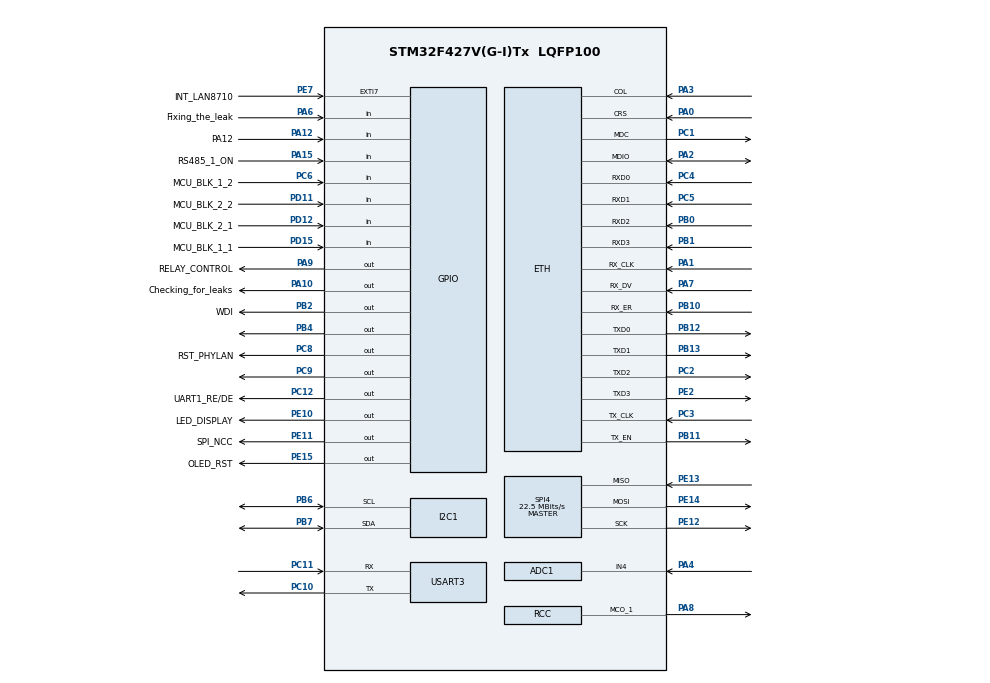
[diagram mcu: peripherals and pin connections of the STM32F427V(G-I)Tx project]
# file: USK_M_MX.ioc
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ADC1.Channel-0\#ChannelRegularConversion=ADC_CHANNEL_4
ADC1.NbrOfConversionFlag=1
ADC1.Rank-0\#ChannelRegularConversion=1
ADC1.SamplingTime-0\#ChannelRegularConversion=ADC_SAMPLETIME_3CYCLES
ADC1.master=1
Dma.Request0=SPI4_TX
Dma.Request1=USART3_RX
Dma.Request2=USART3_TX
Dma.SPI4_TX.0.Direction=DMA_MEMORY_TO_PERIPH
Dma.SPI4_TX.0.FIFOMode=DMA_FIFOMODE_DISABLE
Dma.SPI4_TX.0.Instance=DMA2_Stream1
Dma.SPI4_TX.0.MemDataAlignment=DMA_MDATAALIGN_BYTE
Dma.SPI4_TX.0.MemInc=DMA_MINC_ENABLE
Dma.SPI4_TX.0.Mode=DMA_NORMAL
Dma.SPI4_TX.0.PeriphDataAlignment=DMA_PDATAALIGN_BYTE
Dma.SPI4_TX.0.PeriphInc=DMA_PINC_DISABLE
Dma.SPI4_TX.0.Priority=DMA_PRIORITY_LOW
Dma.USART3_RX.1.Direction=DMA_PERIPH_TO_MEMORY
Dma.USART3_RX.1.FIFOMode=DMA_FIFOMODE_DISABLE
Dma.USART3_RX.1.Instance=DMA1_Stream1
Dma.USART3_RX.1.MemDataAlignment=DMA_MDATAALIGN_BYTE
Dma.USART3_RX.1.MemInc=DMA_MINC_ENABLE
Dma.USART3_RX.1.Mode=DMA_NORMAL
Dma.USART3_RX.1.PeriphDataAlignment=DMA_PDATAALIGN_BYTE
Dma.USART3_RX.1.PeriphInc=DMA_PINC_DISABLE
Dma.USART3_RX.1.Priority=DMA_PRIORITY_LOW
Dma.USART3_TX.2.Direction=DMA_MEMORY_TO_PERIPH
Dma.USART3_TX.2.FIFOMode=DMA_FIFOMODE_DISABLE
Dma.USART3_TX.2.Instance=DMA1_Stream3
Dma.USART3_TX.2.MemDataAlignment=DMA_MDATAALIGN_BYTE
Dma.USART3_TX.2.MemInc=DMA_MINC_ENABLE
Dma.USART3_TX.2.Mode=DMA_NORMAL
Dma.USART3_TX.2.PeriphDataAlignment=DMA_PDATAALIGN_BYTE
Dma.USART3_TX.2.PeriphInc=DMA_PINC_DISABLE
Dma.USART3_TX.2.Priority=DMA_PRIORITY_LOW
ETH.MediaInterface=HAL_ETH_MII_MODE
FREERTOS.Tasks01=defaultTask,24,1280,StartDefaultTask,Default,NULL,Dynamic,NULL,NULL;Relay_task,24,1280,StartTask02,Default,NULL,Dynamic,NULL,NULL;mobdus,24,1280,StartTask03,Default,NULL,Dynamic,NULL,NULL;Relay_control,24,250,StartTask04,Default,NULL,Dynamic,NULL,NULL;LWGL_control,24,2500,StartTask05,Default,NULL,Dynamic,NULL,NULL;WDI,24,128,StartTask06,Default,NULL,Dynamic,NULL,NULL
FREERTOS.configQUEUE_REGISTRY_SIZE=20
FREERTOS.configTOTAL_HEAP_SIZE=37768
LWIP.BSP.number=1
LWIP.DEFAULT_THREAD_STACKSIZE=2048
LWIP.GATEWAY_ADDRESS=192.168.070.001
LWIP.IP_ADDRESS=192.168.070.040
LWIP.LWIP_DHCP=0
LWIP.LWIP_HTTPD=1
LWIP.LWIP_HTTPD_CGI=1
LWIP.LWIP_HTTPD_SSI=1
LWIP.LWIP_HTTPD_SSI_BY_FILE_EXTENSION=0
LWIP.LWIP_STATS=1
LWIP.MEMP_NUM_TCP_PCB=15
LWIP.MEMP_NUM_TCP_PCB_LISTEN=15
LWIP.MEM_SIZE=40960
LWIP.NETMASK_ADDRESS=255.255.255.000
LWIP.PBUF_POOL_SIZE=50
LWIP.TCPIP_THREAD_STACKSIZE=2048
LWIP.TCP_MSS=1458
LWIP.TCP_WND=11664
LWIP.Version=v2.1.2_Cube
LWIP0.BSP.STBoard=false
LWIP0.BSP.api=BSP_COMPONENT_DRIVER
LWIP0.BSP.component=DP83848
LWIP0.BSP.instance=DP83848
LWIP0.BSP.name=Driver_PHY
LWIP0.BSP.semaphore=S_DP83848
LWIP0.BSP.solution=DP83848
Mcu.Family=STM32F4
Mcu.Name=STM32F427V(G-I)Tx
Mcu.Package=LQFP100
NVIC.DMA1_Stream1_IRQn=true\:5\:0\:false\:false\:true\:true\:false\:true\:true
NVIC.DMA1_Stream3_IRQn=true\:5\:0\:false\:false\:true\:true\:false\:true\:true
NVIC.DMA2_Stream1_IRQn=true\:5\:0\:false\:false\:true\:true\:false\:true\:true
NVIC.ETH_IRQn=true\:5\:0\:false\:false\:true\:true\:false\:true\:true
NVIC.PriorityGroup=NVIC_PRIORITYGROUP_4
NVIC.TIM1_UP_TIM10_IRQn=true\:15\:0\:false\:false\:true\:false\:false\:true\:true
NVIC.TIM2_IRQn=true\:5\:0\:false\:false\:true\:true\:true\:true\:true
NVIC.TimeBase=TIM1_UP_TIM10_IRQn
NVIC.TimeBaseIP=TIM1
NVIC.USART3_IRQn=true\:5\:0\:false\:false\:true\:true\:true\:true\:true
PA0/WKUP.Mode=MII
PA0/WKUP.Signal=ETH_CRS
PA1.Mode=MII
PA1.Signal=ETH_RX_CLK
PA10.GPIO_Label=Checking_for_leaks
PA10.Signal=GPIO_Output
PA12.GPIO_Label=PA12
PA12.Signal=GPIO_Input
PA13.Mode=Serial_Wire
PA13.Signal=SYS_JTMS-SWDIO
PA14.Mode=Serial_Wire
PA14.Signal=SYS_JTCK-SWCLK
PA15.GPIO_Label=RS485_1_ON
PA15.Signal=GPIO_Input
PA2.Mode=MII
PA2.Signal=ETH_MDIO
PA3.Mode=MII
PA3.Signal=ETH_COL
PA4.Signal=ADCx_IN4
PA6.GPIO_Label=Fixing_the_leak
PA6.Signal=GPIO_Input
PA7.Mode=MII
PA7.Signal=ETH_RX_DV
PA8.Mode=Clock-out-1
PA8.Signal=RCC_MCO_1
PA9.GPIO_Label=RELAY_CONTROL
PA9.Signal=GPIO_Output
PB0.Mode=MII
PB0.Signal=ETH_RXD2
PB1.Mode=MII
PB1.Signal=ETH_RXD3
PB10.Mode=Activate Rx Err signal
PB10.Signal=ETH_RX_ER
PB11.Mode=MII
PB11.Signal=ETH_TX_EN
PB12.Mode=MII
PB12.Signal=ETH_TXD0
PB13.Mode=MII
PB13.Signal=ETH_TXD1
PB2/BOOT1.GPIO_Label=WDI
PB2/BOOT1.Signal=GPIO_Output
PB4.Signal=GPIO_Output
PB6.Mode=I2C
PB6.Signal=I2C1_SCL
PB7.Mode=I2C
PB7.Signal=I2C1_SDA
PC1.Mode=MII
PC1.Signal=ETH_MDC
PC10.Mode=Asynchronous
PC10.Signal=USART3_TX
PC11.Mode=Asynchronous
PC11.Signal=USART3_RX
PC12.GPIO_Label=UART1_RE/DE
PC12.Signal=GPIO_Output
PC2.Mode=MII
PC2.Signal=ETH_TXD2
PC3.Mode=MII
PC3.Signal=ETH_TX_CLK
PC4.Mode=MII
PC4.Signal=ETH_RXD0
PC5.Mode=MII
PC5.Signal=ETH_RXD1
PC6.GPIO_Label=MCU_BLK_1_2
PC6.Signal=GPIO_Input
PC8.GPIO_Label=RST_PHYLAN
PC8.Signal=GPIO_Output
PC9.Signal=GPIO_Output
PD11.GPIO_Label=MCU_BLK_2_2
PD11.Signal=GPIO_Input
PD12.GPIO_Label=MCU_BLK_2_1
PD12.Signal=GPIO_Input
PD15.GPIO_Label=MCU_BLK_1_1
PD15.Signal=GPIO_Input
PE10.GPIO_Label=LED_DISPLAY
PE10.Signal=GPIO_Output
PE11.GPIO_Label=SPI_NCC
PE11.Signal=GPIO_Output
PE12.Mode=Full_Duplex_Master
PE12.Signal=SPI4_SCK
PE13.Mode=Full_Duplex_Master
PE13.Signal=SPI4_MISO
PE14.Mode=Full_Duplex_Master
PE14.Signal=SPI4_MOSI
PE15.GPIO_Label=OLED_RST
PE15.Signal=GPIO_Output
PE2.Mode=MII
PE2.Signal=ETH_TXD3
PE7.GPIO_Label=INT_LAN8710
PE7.Signal=GPXTI7
PH0/OSC_IN.Mode=HSE-External-Oscillator
PH0/OSC_IN.Signal=RCC_OSC_IN
PH1/OSC_OUT.Mode=HSE-External-Oscillator
PH1/OSC_OUT.Signal=RCC_OSC_OUT
ProjectManager.HeapSize=0x4000
ProjectManager.StackSize=0x2000
ProjectManager.TargetToolchain=EWARM V8.50
RCC.48MHZClocksFreq_Value=90000000
RCC.AHBFreq_Value=90000000
RCC.APB1CLKDivider=RCC_HCLK_DIV2
RCC.APB1Freq_Value=45000000
RCC.APB1TimFreq_Value=90000000
RCC.APB2CLKDivider=RCC_HCLK_DIV2
RCC.APB2Freq_Value=45000000
RCC.APB2TimFreq_Value=90000000
RCC.CortexFreq_Value=90000000
RCC.HCLKFreq_Value=90000000
RCC.HSE_VALUE=25000000
RCC.HSI_VALUE=16000000
RCC.LSE_VALUE=32768
RCC.PLLM=15
RCC.PLLN=216
RCC.PLLP=RCC_PLLP_DIV4
RCC.PLLSourceVirtual=RCC_PLLSOURCE_HSE
RCC.RCC_MCO1Source=RCC_MCO1SOURCE_HSE
RCC.SYSCLKFreq_VALUE=90000000
RCC.SYSCLKSource=RCC_SYSCLKSOURCE_PLLCLK
RCC.VCOOutputFreq_Value=360000000
SH.ADCx_IN4.0=ADC1_IN4,IN4
SPI4.CalculateBaudRate=22.5 MBits/s
SPI4.Direction=SPI_DIRECTION_2LINES
SPI4.Mode=SPI_MODE_MASTER
SPI4.VirtualType=VM_MASTER
TIM2.Period=9999
TIM2.Prescaler=17999
USART3.VirtualMode=VM_ASYNC
VP_FREERTOS_VS_CMSIS_V2.Mode=CMSIS_V2
VP_LWIP_VS_Enabled.Mode=Enabled
VP_SYS_VS_tim1.Mode=TIM1
VP_TIM2_VS_ClockSourceINT.Mode=Internal
board=custom

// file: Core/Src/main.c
/* USER CODE BEGIN Header */
/**
  ******************************************************************************
  * @file           : main.c
  * @brief          : Main program body
  ******************************************************************************
  * @attention
  *
  * Copyright (c) 2024 STMicroelectronics.
  * All rights reserved.
  *
  * This software is licensed under terms that can be found in the LICENSE file
  * in the root directory of this software component.
  * If no LICENSE file comes with this software, it is provided AS-IS.
  *
  ******************************************************************************
  */
/* USER CODE END Header */
#include "main.h"
#include "cmsis_os.h"
#include "adc.h"
#include "dma.h"
#include "i2c.h"
#include "lwip.h"
#include "spi.h"
#include "tim.h"
#include "usart.h"
#include "gpio.h"

/* USER CODE BEGIN Includes */
#include "api.h"
#include "modbus.h"
#include "FreeRTOS.h"
#include "semphr.h"
#include "lwip/apps/fs.h"
#include "timers.h"
#include <string.h>
/* USER CODE END Includes */

/* USER CODE BEGIN PD */

extern uint8_t USART_3_SPEED[10];
extern uint8_t uartStopBits[10];
extern uint8_t uartPARITY[10];

uint32_t usart_speed = 0;

#define START_ADDR 0x08020000

uint8_t ucHeap[configTOTAL_HEAP_SIZE] @ ".ccmram" = {0};;

/* USER CODE END PD */

void SystemClock_Config(void);
void MX_FREERTOS_Init(void);
/* USER CODE BEGIN PFP */
void vTimerCallback(TimerHandle_t xTimer);
static void ProtectBootSectorsOnce(void);
extern void ReadFlash(FlashDataType type, uint8_t* buffer);
/* USER CODE END PFP */

int main(void)
{
  /* USER CODE BEGIN 1 */
  __disable_irq();
  SCB->VTOR = START_ADDR;
  __enable_irq();
  /* USER CODE END 1 */

  /* MCU Configuration--------------------------------------------------------*/

  /* Reset of all peripherals, Initializes the Flash interface and the Systick. */
  HAL_Init();

  /* Configure the system clock */
  SystemClock_Config();

  /* Initialize all configured peripherals */

  MX_GPIO_Init();

  __HAL_RCC_DMA1_FORCE_RESET();
  __HAL_RCC_DMA1_RELEASE_RESET();

  MX_DMA_Init();
  MX_SPI4_Init();
  MX_ADC1_Init();
  MX_TIM2_Init();

  ProtectBootSectorsOnce();

  uint8_t TEST[10] = {0};
  //uint8_t test = 0;

  ReadFlash(RS485SPEED, TEST);
  for (uint8_t i = 0; i < 4; i++) {
    if (TEST[i] != 0xFF) {
      //test = 1;
      ReadFlash(RS485SPEED, USART_3_SPEED);
      if ((USART_3_SPEED[0] == 0x31) && (USART_3_SPEED[1] == 0x32)) {
        usart_speed = 1200;
      } else if ((USART_3_SPEED[0] == 0x39) && (USART_3_SPEED[1] == 0x36)) {
        usart_speed = 9600;
      } else if ((USART_3_SPEED[0] == 0x31) && (USART_3_SPEED[1] == 0x39)) {
        usart_speed = 19200;
      } else if ((USART_3_SPEED[0] == 0x33) && (USART_3_SPEED[1] == 0x38)) {
        usart_speed = 38400;
      } else if ((USART_3_SPEED[0] == 0x35) && (USART_3_SPEED[1] == 0x37)) {
        usart_speed = 57600;
      } else if ((USART_3_SPEED[0] == 0x31) && (USART_3_SPEED[1] == 0x31)) {
        usart_speed = 115200;
      }
    } else {
      usart_speed = 115200;
    }
  }

/*
  if (test == 1) {
  ReadFlash(RS485SPEED, USART_3_SPEED);
  if ((USART_3_SPEED[0] == 0x31) && (USART_3_SPEED[1] == 0x32)) {
    usart_speed = 1200;
  } else if ((USART_3_SPEED[0] == 0x39) && (USART_3_SPEED[1] == 0x36)) {
    usart_speed = 9600;
  } else if ((USART_3_SPEED[0] == 0x31) && (USART_3_SPEED[1] == 0x39)) {
    usart_speed = 19200;
  } else if ((USART_3_SPEED[0] == 0x33) && (USART_3_SPEED[1] == 0x38)) {
    usart_speed = 38400;
  } else if ((USART_3_SPEED[0] == 0x35) && (USART_3_SPEED[1] == 0x37)) {
    usart_speed = 57600;
  } else if ((USART_3_SPEED[0] == 0x31) && (USART_3_SPEED[1] == 0x31)) {
    usart_speed = 115200;
  }
    test = 0;
  } else {
    usart_speed = 115200;
  }
*/

  ReadFlash(RS485PARITIY, TEST);
  for (uint8_t i = 0; i < 4; i++) {
    if (TEST[i] != 0xFF) {
      //test = 1;
      ReadFlash(RS485PARITIY, uartPARITY);
    } else {
      strcpy((char *)uartPARITY, "none");
    }
  }

/*
  if (test == 1) {
    ReadFlash(RS485PARITIY, uartPARITY);
    test = 0;
  } else {
    strcpy((char *)uartPARITY, "none");
  }
*/

  ReadFlash(RS485STOPBIT, TEST);
  for (uint8_t i = 0; i < 4; i++) {
    if (TEST[i] != 0xFF) {
      //test = 1;
      ReadFlash(RS485STOPBIT, uartStopBits);
    } else {
      uartStopBits[0] = 1;
    }
  }
  /*
  if(test == 1) {
    ReadFlash(RS485STOPBIT, uartStopBits);
    test = 0;
  } else {
    uartStopBits[0] = 1;
  }
  */

  MX_USART3_UART_Init();
  MX_I2C1_Init();
  /* USER CODE BEGIN 2 */
  HAL_TIM_Base_Start_IT(&htim2);

  /* Init scheduler */
  osKernelInitialize();

  /* Call init function for freertos objects (in cmsis_os2.c) */
  MX_FREERTOS_Init();
  TimerHandle_t xTimer = xTimerCreate("Timer", pdMS_TO_TICKS(1000), pdTRUE, 0, vTimerCallback);

  if (xTimer != NULL) {
    xTimerStart(xTimer, 0);
  }

  /* Start scheduler */
  osKernelStart();

  /* We should never get here as control is now taken by the scheduler */

  /* Infinite loop */
  while (1)
  {

  }
}

void SystemClock_Config(void)
{
  RCC_OscInitTypeDef RCC_OscInitStruct = {0};
  RCC_ClkInitTypeDef RCC_ClkInitStruct = {0};

  /** Configure the main internal regulator output voltage
  */
  __HAL_RCC_PWR_CLK_ENABLE();
  __HAL_PWR_VOLTAGESCALING_CONFIG(PWR_REGULATOR_VOLTAGE_SCALE1);  //scale3 is normal on 90mhz  ------------------------------

  /** Initializes the RCC Oscillators according to the specified parameters
  * in the RCC_OscInitTypeDef structure.
  */
  RCC_OscInitStruct.OscillatorType = RCC_OSCILLATORTYPE_HSE;
  RCC_OscInitStruct.HSEState = RCC_HSE_ON;
  RCC_OscInitStruct.PLL.PLLState = RCC_PLL_ON;
  RCC_OscInitStruct.PLL.PLLSource = RCC_PLLSOURCE_HSE;
  RCC_OscInitStruct.PLL.PLLM = 15;
  RCC_OscInitStruct.PLL.PLLN = 216;
  RCC_OscInitStruct.PLL.PLLP = RCC_PLLP_DIV2;
  RCC_OscInitStruct.PLL.PLLQ = 4;
  if (HAL_RCC_OscConfig(&RCC_OscInitStruct) != HAL_OK)
  {
    Error_Handler();
  }

  /** Activate the Over-Drive mode
  */
  if (HAL_PWREx_EnableOverDrive() != HAL_OK)
  {
    Error_Handler();
  }

  /** Initializes the CPU, AHB and APB buses clocks
  */
  RCC_ClkInitStruct.ClockType = RCC_CLOCKTYPE_HCLK|RCC_CLOCKTYPE_SYSCLK
                              |RCC_CLOCKTYPE_PCLK1|RCC_CLOCKTYPE_PCLK2;
  RCC_ClkInitStruct.SYSCLKSource = RCC_SYSCLKSOURCE_PLLCLK;
  RCC_ClkInitStruct.AHBCLKDivider = RCC_SYSCLK_DIV1;
  RCC_ClkInitStruct.APB1CLKDivider = RCC_HCLK_DIV4;
  RCC_ClkInitStruct.APB2CLKDivider = RCC_HCLK_DIV2;

  if (HAL_RCC_ClockConfig(&RCC_ClkInitStruct, FLASH_LATENCY_5) != HAL_OK)  //latency 2 is normal on 90mhz
  {
    Error_Handler();
  }
  HAL_RCC_MCOConfig(RCC_MCO1, RCC_MCO1SOURCE_HSE, RCC_MCODIV_1);
}

/* USER CODE BEGIN 4 */

static void ProtectBootSectorsOnce(void)
{
  FLASH_OBProgramInitTypeDef ob = {0};

  HAL_FLASH_OB_Unlock();
  HAL_FLASHEx_OBGetConfig(&ob);

  uint32_t want = OB_WRP_SECTOR_0 | OB_WRP_SECTOR_1 | OB_WRP_SECTOR_2;
  if ((ob.WRPSector & want) == want)
  {
    HAL_FLASH_OB_Lock();
    return;
  }

  ob.OptionType = OPTIONBYTE_WRP;
  ob.WRPState   = OB_WRPSTATE_ENABLE;
  ob.WRPSector |= want;

  HAL_FLASH_Unlock();
  if (HAL_FLASHEx_OBProgram(&ob) != HAL_OK)
    Error_Handler();

  HAL_FLASH_OB_Launch();
}

/* USER CODE END 4 */

void HAL_TIM_PeriodElapsedCallback(TIM_HandleTypeDef *htim)
{
  if (htim->Instance == TIM1) {
    HAL_IncTick();
  }
}

void Error_Handler(void)
{
  __disable_irq();
  while (1)
  {
  }
}

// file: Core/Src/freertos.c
/* USER CODE BEGIN Header */
/**
******************************************************************************
* File Name          : freertos.c
* Description        : Code for freertos applications
******************************************************************************
* @attention
*
* Copyright (c) 2024 STMicroelectronics.
* All rights reserved.
*
* This software is licensed under terms that can be found in the LICENSE file
* in the root directory of this software component.
* If no LICENSE file comes with this software, it is provided AS-IS.
*
******************************************************************************
*/
/* USER CODE END Header */

#include "FreeRTOS.h"
#include "task.h"
#include "main.h"
#include "cmsis_os.h"

/* USER CODE BEGIN Includes */
#include "modbus.h"
#include "lwip.h"
#include "semphr.h"
#include "lwip/netif.h"
#include "lwip/api.h"
#include "lwip/apps/fs.h"
#include "lwip/apps/httpd.h"

#include <stdio.h>
#include <stdint.h>
#include <stdlib.h>
#include <string.h>
#include "adc.h"
#include "timers.h"
#include "stm32f4xx_hal.h"
#include "stm32f4xx_hal_rtc.h"
#include "stm32f4xx.h"
#include "dp83848.h"

#include "measurement.h"

/* USER CODE END Includes */
#include "lwip/tcp.h"
#include "test.h"

/* USER CODE BEGIN PD */

osMutexId_t RelayMutexHandle;  //защита общего регистра REGISTERS[2] (состояние реле)
SemaphoreHandle_t xHighPrioritySemaphore; //будить HighPriorityTask по готовности ADC

extern struct netif gnetif;
extern UART_HandleTypeDef huart3;

//буфер приёма для HAL_UARTEx_ReceiveToIdle_DMA
uint8_t rxBuffer[50] = {0};

volatile uint16_t REGISTERS[9] = {0};

extern uint32_t usart_speed;

uint8_t SERIAL_ADDRESS[6] = {0};

extern void MX_USART3_UART_Init(void);
//----------------------------ADC---LOGIC---------------------------------------

volatile uint8_t last_position = 5; //кеш последнего реально установленного
                                    //состояния реле (0 — выкл, 1 — вкл)

volatile uint8_t mode = 0;          // Ручное или автоматическое управление реле
uint8_t reley_auto_protection = 1;  // Ручное или автоматическое управление реле

volatile uint8_t log_ready = 0;     //можно ли сейчас писать лог в флеш

static TimerHandle_t xTestBlockTimer = NULL;    //Не дает бесконечно зажимать тест
                                                //      (перегрев)
TimerHandle_t xRelayFlagTimer = NULL;    //индикация срабатывания (10мин)
TimerHandle_t xStartADCtimer = NULL;    //задержка старта измерений
void vRelayFlagCallback(TimerHandle_t xTimer);

volatile uint8_t button_event = 0;       //событие кнопки ТЕСТ получено
volatile uint8_t button_block = 0; // блок повторных срабатываний

float C_phase_A = 0;
float R_leak_A = 0;
float C_phase_B = 0;
float R_leak_B = 0;
float C_phase_C = 0;
float R_leak_C = 0;

uint8_t TARGET_VALUE = 25;
uint8_t TARGET_VALUE_DEF = 25;

uint8_t WARNING_VALUE = 20;
uint8_t WARNING_VALUE_DEF = 20;

volatile uint16_t adc_window_ms = 10;
uint16_t adc_window_ms_def = 10;
volatile uint8_t adc_min_exceed = 0;
uint8_t adc_min_exceed_def = 0;

//uint8_t hw_protection = 0;
#define FLASH_ADDRESS_C_PHASE_A 0x0800C0A0
#define FLASH_ADDRESS_R_LEAK_A  0x0800C0B0
#define FLASH_ADDRESS_C_PHASE_B 0x0800C0C0
#define FLASH_ADDRESS_R_LEAK_B  0x0800C0D0
#define FLASH_ADDRESS_C_PHASE_C 0x0800C0E0
#define FLASH_ADDRESS_R_LEAK_C  0x0800C0F0
#define FLASH_ADDRESS_TARGET_VALUE 0x0800C100
#define FLASH_ADDRESS_HW_PROTECTION 0x0800C110
#define FLASH_ADDRESS_WARNING_VALUE 0x0800C120
#define FLASH_ADDRESS_RELAY_TIME 0x0800C130
#define FLASH_ADDRESS_ADC_WINDOW 0x0800C140
#define FLASH_ADDRESS_ADC_MIN_EXCEED 0x0800C150

//------------------------------------------------------------------------------

uint8_t USART_3_SPEED[10];
uint8_t uartStopBits[10];
char uartPARITY[10];
uint8_t output[200] = {0};

volatile uint16_t neead_write_flash = 0; //Отложенная запись WriteFlash(0,0)

//-------------------------------------------------------------------
uint8_t SOFTWARE_VERSION[3] = {1, 1, 67};
uint16_t soft_ver_modbus = 119;

volatile uint8_t test_leak = 0;

extern struct httpd_state *hs;

/* USER CODE END PD */

/* USER CODE BEGIN PM */
struct netconn * nc;
struct netconn * in_nc;
struct netbuf * nb;
struct netconn *newconn = NULL;

const char *ssi_tags[] = {"MAC", "IP", "MASK", "GETAWEY", "AMP", "SEC", "MIN",
"HOUR", "DAY", "PIN", "RELAY", "SERIAL", "SOFT", "RS485", "SPEED", "PARITY",
"STOPB", "CPHASEA", "RLEAKA", "CPHASEB", "RLEAKB", "CPHASEC", "RLEAKC", "TVALUE", "MODE"
, "CRCACC", "JSON", "WVALUE", "ALERT", "LOG", "RELTIM", "LOGRST", "ADCWIN", "ADCEXC"};

//---------------------------------------FLASH-OS----------------------------------------------------
static uint32_t address = 0;
static uint32_t len = 0;
static uint32_t next_free_addr = 0;
//---------------------------------------------------------------------------------------------------
extern volatile uint8_t theme;

volatile uint8_t relay_pause = 0;
volatile uint8_t protection_pause = 0;   // дефолштная пауза
volatile uint16_t relay_timeout = 250;  // пауза после срабатывания

//PA6_in
#define FIXING_THE_LEAK_PIN        GPIO_PIN_6
#define FIXING_THE_LEAK_PORT       GPIOA

//PA10_in
#define CHECKING_FOR_LEAKS_PIN     GPIO_PIN_10
#define CHECKING_FOR_LEAKS_PORT    GPIOA

//PA12_in
#define NO_NAME_PIN_PIN            GPIO_PIN_12
#define NO_NAME_PIN_PORT           GPIOA

#define MAC_SIZE 16
#define IP_SIZE 16
#define NETMASK_SIZE 16
#define GATEWAY_SIZE 16
#define SERIAL_SIZE 16
uint8_t PIN[6] = {0x34, 0x37, 0x32, 0x32, 0x30, 0x31};   // pin in ASCII - 4-7-2-2-0-1
uint8_t pinaccept = 0;

#define FLASH_ADDRESS_MAC 0x0800C000
#define FLASH_ADDRESS_IP  0x0800C010
#define FLASH_ADDRESS_NETMASK 0x0800C020
#define FLASH_ADDRESS_GATEWAY 0x0800C030
#define FLASH_ADDRESS_SERIAL 0x0800C040

#define FLASH_ADDRESS_RS485_SPEED 0x0800C050
#define FLASH_ADDRESS_RS485_PARITIY 0x0800C060
#define FLASH_ADDRESS_RS485_STOPBIT 0x0800C070
#define TIMEOUT_MS 8000

#define BOOT_OS_OK_ADDRESS 0x0800C080
#define BOOT_CRC_ADDRESS 0x0800C200
#define BOOT_FLAG_NEW_ADDRESS 0x0800C084
//#define SECTOR_1_ADDRESS 0x08020000 //end in 0x08080000 (sector 5/6/7) 384kb in total

#define SECTOR_8_ADDRESS 0x08080000 // end in 0x080E0000 (sector 8/9/10) 384kb in total

#define BOOTLOADER_ADDRESS 0x08000000 //end in 0x0800C080  48kb in total
#define SECTOR_ENABLED_ADDRESS 0x0800C088 //1 - нет новой ОС, 2 - есть новоя ОС
#define LOG_SECTOR_ACTIVE 0x0800C204 //в каком секторе мы пишем лог сейчас

#define LOG_START_ADDR_BLOCK 0x08120000  //17-23 sectors (128х7)
#define LOG_END_ADDR_BLOCK 0x081FFFF8
#define LOG_ENTRY_SIZE  (12U)

#define TIME_FLAG_SET   (1U << 2)  // bit2: время установлено
#define TIME_FLAG_APPLY (1U << 3)  // bit3: попросить применить время

#define MINUTE_10_SIZE 10
#define HOUR_1_SIZE 6
#define DAY_2_SIZE 48

volatile uint16_t avg1h = 0;
volatile uint16_t avg2d = 0;

//-------------------------TIME-&-LOG--SECTION---------------------------------------
UBaseType_t WM_LWIP;
UBaseType_t WM_ADC;
UBaseType_t WM_MODBUS;
UBaseType_t WM_OLED;
UBaseType_t WM_WDI;
UBaseType_t WM_RELAY;

UBaseType_t uxHighWaterMark2;

typedef struct {
  uint8_t seconds;   // 0-59
  uint8_t minutes;   // 0-59
  uint8_t hours;     // 0-23 (24-часовой формат)
  uint8_t day;       // 1-31 (день месяца)
  uint8_t month;     // 1-12
  uint16_t year;     // Пример: 2023 (полный год)   //not used
} DateTime;

typedef struct {
  uint8_t timestamp[6];  // ss:mm:hh:dd:mm:yy (временная метка)
  uint8_t event_code;    // код события
  uint8_t data[5];       //поле данных
} LogEntry;
                           //12 байт

volatile uint32_t log_ptr = 0;  //Указатель на ячейку лога для записи
                                //Если он равен 0, то лог пишется в память загрузчика

RTC_HandleTypeDef hrtc;

volatile uint32_t LOG_START_ADDR = 0;
volatile uint32_t LOG_END_ADDR = 0;

volatile uint8_t log_sector_active = 0;

#define LOG_BUFF_SIZE 1026
volatile uint8_t log_for_wed[LOG_BUFF_SIZE] = {0};

static int first_call = 1;

//--------------------------(critical flags)------------------------------------
//после изменения этих флагов нужно вызвать WriteFlash(0, 0);
//для их автоматической запиши во флеш
volatile uint8_t boot_os_ok = 0;
volatile uint8_t boot_flag_new = 0;
volatile uint8_t sector_enabled = 0;
volatile uint32_t crc_os = 0;
volatile uint8_t crc_accepted = 5;
//------------------------------------------------------------------------------

uint8_t restart = 0; //нужно перезагрузиться после изменения настроек
SemaphoreHandle_t xPacketSemaphore;
SemaphoreHandle_t xPacketSaved;
CRC_HandleTypeDef hcrc;
uint16_t start = 1;  //флаг того, что у нас фаза запуска
uint8_t OLED_RESET = 1;
volatile uint8_t RS485 = 0;
volatile uint32_t er = 0;
uint8_t response_data[50] = {0}; //Общий буфер для ответов Modbus

volatile uint8_t flash_block = 0;

//-------------------------------------------------------------------------------------------------------------------
typedef struct {
    uint16_t arr[MINUTE_10_SIZE];
    uint8_t index;
    uint32_t sum;
} CircularBuffer10Min;

typedef struct {
    uint16_t arr[HOUR_1_SIZE];
    uint8_t index;
    uint32_t sum;
} CircularBuffer1Hour;

typedef struct {
    uint16_t arr[DAY_2_SIZE];
    uint8_t index;
    uint32_t sum;
} CircularBuffer2Day;

/* USER CODE END PM */

osThreadId_t HighPriorityTaskHandle;
const osThreadAttr_t HighPriorityTask_attributes = {
   .name = "HighPriorityTask",
   .stack_size = 7000, // Размер стека (измените при необходимости)
   .priority = (osPriority_t) osPriorityAboveNormal, // Приоритет выше остальных
};

/* Definitions for defaultTask */
osThreadId_t defaultTaskHandle;
const osThreadAttr_t defaultTask_attributes = {
  .name = "defaultTask",
  .stack_size = 1248 * 4,
  .priority = (osPriority_t) osPriorityNormal,
};

/* Definitions for Relay_task */
osThreadId_t Relay_taskHandle;
const osThreadAttr_t Relay_task_attributes = {
  .name = "Relay_task",
  .stack_size = 1128 * 6,
  .priority = (osPriority_t) osPriorityNormal,
};
/* Definitions for mobdus */
osThreadId_t mobdusHandle;
const osThreadAttr_t mobdus_attributes = {
  .name = "mobdus",
  .stack_size = 1500 * 4,
  .priority = (osPriority_t) osPriorityNormal,
};
/* Definitions for Relay_control */
osThreadId_t Relay_controlHandle;
const osThreadAttr_t Relay_control_attributes = {
  .name = "Relay_control",
  .stack_size = 1128 * 4,
  .priority = (osPriority_t) osPriorityNormal1,
};
/* Definitions for LWGL_control */
osThreadId_t LWGL_controlHandle;
const osThreadAttr_t LWGL_control_attributes = {
  .name = "LWGL_control",
  .stack_size = 4200,
  .priority = (osPriority_t) osPriorityNormal, //osPriorityNormal
};
/* Definitions for WDI */
osThreadId_t WDIHandle;
const osThreadAttr_t WDI_attributes = {
  .name = "WDI",
  .stack_size = 528,
  .priority = (osPriority_t) osPriorityNormal,
};

/* USER CODE BEGIN FunctionPrototypes */
void httpd_ssi_init(void);
uint16_t ssi_handler(int iIndex, char *pcInsert, int iInsertLen);
void ReadFlash(FlashDataType type, uint8_t* buffer);
void WriteFlash(FlashDataType type, uint8_t* data);
void convert_str_to_uint8_array(const char* input, uint8_t* output, int is_mac);
void send_uart(const uint8_t *response, uint16_t len);
void DrawCenteredSemiCircle2(UWORD percent);
void DrawCenteredSemiCircle();
void startMyTimer_RESET(uint32_t timeout_ms);
void vMyTimerCallback(TimerHandle_t xTimer);
void convert_str_to_uint8_array_serial(const char* input, uint8_t* output);
void EXTI12_Init(void);
void EXTI15_10_IRQHandler(void);
void log_for_web_init();
void Swipe_Log_Sector();
void WriteToFlash(uint32_t startAddress, uint8_t* data, uint32_t length);
void load_flags_from_flash(void);
HAL_StatusTypeDef Flash_WritePacket(uint8_t *packet, uint16_t packet_size);
char* extract_body(uint8_t *packet);
void RTC_Init(void);
uint32_t find_next_free_log_address(void);
void convert_str_to_float_bytes(const char* input, uint8_t* output);
void load_values_from_flash(void);
void send_ethernet(uint8_t *data, uint16_t len, struct netconn *newconn);
uint16_t adc_get_rms(uint16_t *arr, uint16_t length);
void CleanupResources(struct netconn *nc, struct netconn *newconn, struct netbuf *buf);

//void write_to_log(uint8_t code, uint8_t log_data[], uint16_t copy_len);
void write_to_log(log_code code, uint8_t log_data[], uint16_t copy_len);

static uint8_t RTC_IsTimeValid(void);
void save_time_to_rtc(uint8_t* arr);
uint32_t calculate_flash_crc(uint32_t start_address, uint32_t end_address);
void CRC_Config(void);
uint16_t parser_num(uint8_t *buf, uint16_t len, const char *str);
uint8_t * parser(uint8_t *buf, uint16_t len, const char *str);
void get_current_timestamp(uint8_t *timestamp);
void initBuffer10Min(CircularBuffer10Min *buffer);
void initBuffer1Hour(CircularBuffer1Hour *buffer);
void initBuffer2Day(CircularBuffer2Day *buffer);
void addValue10Min(CircularBuffer10Min *buffer, uint16_t value);
void addValue1Hour(CircularBuffer1Hour *buffer, uint16_t value);
void addValue2Day(CircularBuffer2Day *buffer, uint16_t value);
uint16_t getAverage10Min(CircularBuffer10Min *buffer);
uint16_t getAverage1Hour(CircularBuffer1Hour *buffer);
uint16_t getAverage2Day(CircularBuffer2Day *buffer);
void timerCreate(void);
void timerStart(void);

void timerStartCreate(void);
void vStartADCtimerCallback(TimerHandle_t xTimer);
static void vTestBlockReleaseCb(TimerHandle_t xTimer);

err_t httpd_post_begin(void *connection, const char *uri, const char *http_request,
                       u16_t http_request_len, int content_len, char *response_uri,
                       u16_t response_uri_len, u8_t *post_auto_wnd);
err_t httpd_post_receive_data(void *connection, struct pbuf *p);
void httpd_post_finished(void *connection, char *response_uri, u16_t response_uri_len);

extern void OLED_1in5_rgb_run();

const char * SAVE_CGI_Handler(int iIndex, int iNumParams, char *pcParam[], char *pcValue[]);
const char * JSON_CGI_Handler(int iIndex, int iNumParams, char *pcParam[], char *pcValue[]);
const char * LOG_CGI_Handler(int iIndex, int iNumParams, char *pcParam[], char *pcValue[]);

const tCGI SAVE_CGI = {"/save", SAVE_CGI_Handler};
const tCGI JSON_CGI = {"/json", JSON_CGI_Handler};
const tCGI LOG_CGI = {"/logdata", LOG_CGI_Handler};

tCGI CGI_TAB[3];
/* USER CODE END FunctionPrototypes */

void StartDefaultTask(void *argument);
void StartTask02(void *argument);
void StartTask03(void *argument);
void StartTask04(void *argument);
void StartTask05(void *argument);
void StartTask06(void *argument);
void HighPriorityTask(void *argument);

uint8_t save_time_unix(uint64_t timestamp);
void apply_time_from_registers(void);
extern void MX_LWIP_Init(void);
void MX_FREERTOS_Init(void);

extern uint8_t IP_ADDRESS[4];
extern uint8_t NETMASK_ADDRESS[4];
extern uint8_t GATEWAY_ADDRESS[4];

extern uint8_t MACAddr[6];

typedef struct
{
  uint8_t seconds;
  uint8_t minutes;
  uint8_t hours;
  uint16_t days;
} TimeStruct;

TimeStruct time = {0};
TimeStruct time_raw = {0};

void vTimerCallback(TimerHandle_t xTimer)
{
  time_raw.seconds++;

  if (time_raw.seconds >= 60) {
    time_raw.seconds = 0;
    time_raw.minutes++;
    REGISTERS[3] = (time_raw.minutes + (time_raw.hours * 60) + (time_raw.days * 24 * 60));

    if (time_raw.minutes >= 60) {
      time_raw.minutes = 0;
      time_raw.hours++;
      if (time_raw.hours >= 24) {
        time_raw.hours = 0;
        time_raw.days++;
      }
    }
  }

  time.seconds = time_raw.seconds;
  time.minutes = time_raw.minutes;
  time.hours = time_raw.hours;
  time.days = time_raw.days;
}

void MX_FREERTOS_Init(void) {
  /* USER CODE BEGIN Init */

  REGISTERS[2] = 1;

  ReadFlash(SERIAL, SERIAL_ADDRESS);

  IP_ADDRESS[0] = 192;
  IP_ADDRESS[1] = 168;
  IP_ADDRESS[2] = 77;
  IP_ADDRESS[3] = 1;
  NETMASK_ADDRESS[0] = 255;
  NETMASK_ADDRESS[1] = 255;
  NETMASK_ADDRESS[2] = 255;
  NETMASK_ADDRESS[3] = 0;
  GATEWAY_ADDRESS[0] = 192;
  GATEWAY_ADDRESS[1] = 168;
  GATEWAY_ADDRESS[2] = 77;
  GATEWAY_ADDRESS[3] = 254;

  uint8_t TEST[4] = {0};
  //uint8_t test = 0;

  ReadFlash(IP, TEST);
  for (uint8_t i = 0; i < 4; i++) {
    if (TEST[i] != 0xFF) {
      //test = 1;
      ReadFlash(IP, IP_ADDRESS);
    }
  }
/*
  if (test == 1) {
    ReadFlash(IP, IP_ADDRESS);
    test = 0;
  }
*/

  ReadFlash(NETMASK, TEST);
  for (uint8_t i = 0; i < 4; i++) {
    if (TEST[i] != 0xFF) {
      //test = 1;
      ReadFlash(NETMASK, NETMASK_ADDRESS);
    }
  }
/*
  if (test == 1) {
    ReadFlash(NETMASK, NETMASK_ADDRESS);
    test = 0;
  }
*/

  ReadFlash(GATEWAY, TEST);
  for (uint8_t i = 0; i < 4; i++) {
    if (TEST[i] != 0xFF) {
      //test = 1;
      ReadFlash(GATEWAY, GATEWAY_ADDRESS);
    }
  }
/*
  if (test == 1) {
    ReadFlash(GATEWAY, GATEWAY_ADDRESS);
    test = 0;
  }
*/

  MACAddr[0] = 0x00;
  MACAddr[1] = 0x80;
  MACAddr[2] = 0xE1;
  MACAddr[3] = 0x00;
  MACAddr[4] = 0x00;
  MACAddr[5] = 0x00;

  ReadFlash(MAC, TEST);
  for (uint8_t i = 0; i < 4; i++) {
    if (TEST[i] != 0xFF) {
      //test = 1;
      ReadFlash(MAC, MACAddr);
    }
  }
/*
  if (test == 1) {
    ReadFlash(MAC, MACAddr);
    test = 0;
  }
*/

  load_values_from_flash();

  /* USER CODE END Init */

  /* USER CODE BEGIN RTOS_MUTEX */

  xHighPrioritySemaphore = xSemaphoreCreateBinary();
  /* USER CODE END RTOS_MUTEX */

  /* USER CODE BEGIN RTOS_SEMAPHORES */
  /* add semaphores, ... */

  xPacketSemaphore = xSemaphoreCreateBinary();
  xPacketSaved = xSemaphoreCreateBinary();

  /* USER CODE END RTOS_SEMAPHORES */

  /* Create the thread(s) */
  /* creation of defaultTask */

  defaultTaskHandle = osThreadNew(StartDefaultTask, NULL, &defaultTask_attributes);

  /* creation of Relay_task */
  Relay_taskHandle = osThreadNew(StartTask02, NULL, &Relay_task_attributes); //не помогает

  /* creation of mobdus */
  mobdusHandle = osThreadNew(StartTask03, NULL, &mobdus_attributes);  //помогает

  /* creation of Relay_control */
  Relay_controlHandle = osThreadNew(StartTask04, NULL, &Relay_control_attributes); //не помогает

  /* creation of LWGL_control */
  LWGL_controlHandle = osThreadNew(StartTask05, NULL, &LWGL_control_attributes); //не помогает

  /* creation of WDI */
  WDIHandle = osThreadNew(StartTask06, NULL, &WDI_attributes); //помогает

  /* USER CODE BEGIN RTOS_THREADS */
  HighPriorityTaskHandle = osThreadNew(HighPriorityTask, NULL, &HighPriorityTask_attributes); //не помогает
  /* USER CODE END RTOS_THREADS */

}

void StartDefaultTask(void *argument)
{
  /* init code for LWIP */

  /**Блок начальной иициализации**/

  HAL_GPIO_WritePin(RST_PHYLAN_GPIO_Port, RST_PHYLAN_Pin, GPIO_PIN_RESET);
  osDelay(100);
  HAL_GPIO_WritePin(RST_PHYLAN_GPIO_Port, RST_PHYLAN_Pin, GPIO_PIN_SET);  // - PHY init
  osDelay(1);

  MX_LWIP_Init();

  EXTI12_Init();

  while (!netif_is_link_up(&gnetif)) {
    osDelay(100);
  }

  httpd_init();
  httpd_ssi_init();

  __HAL_RCC_CRC_CLK_ENABLE();
  CRC_Config();

  /* USER CODE BEGIN StartDefaultTask */

  CGI_TAB[0] = SAVE_CGI;
  CGI_TAB[1] = JSON_CGI;
  CGI_TAB[2] = LOG_CGI;
  http_set_cgi_handlers(CGI_TAB, 3);

  REGISTERS[0] = soft_ver_modbus;
  HAL_UARTEx_ReceiveToIdle_DMA(&huart3, rxBuffer, sizeof(rxBuffer));
  load_flags_from_flash();

  RTC_Init();
  xSemaphoreGive(xPacketSaved);
  /**Блок начальной иициализации**/

  /* Infinite loop */

  // modbus_RTU
  while (1) {

#if DEBUG == 1
    WM_LWIP = uxTaskGetStackHighWaterMark(NULL);
#endif

    if (REGISTERS[4] & (1 << 4)) {
      // 4-й бит установлен (1)
      mode = 1;
    } else {
      // 4-й бит сброшен (0)
      mode = 0;
    }

    if (xSemaphoreTake(xPacketSemaphore, pdMS_TO_TICKS(1500)) == pdTRUE) {
      uint8_t data[20] = {0};

      uint16_t len_ext = 0;

      uint16_t len = (sizeof(rxBuffer) - __HAL_DMA_GET_COUNTER(huart3.hdmarx));

      memcpy(data, rxBuffer, len);

      modbus(data, len, response_data, &len_ext, RTU);

      send_uart(response_data, len_ext);
    }
/*
    if (
        __HAL_UART_GET_FLAG(&huart3, UART_FLAG_FE)  ||  // Frame Error
          __HAL_UART_GET_FLAG(&huart3, UART_FLAG_NE)  ||  // Noise Error
            __HAL_UART_GET_FLAG(&huart3, UART_FLAG_PE)  ||  // Parity Error
              __HAL_UART_GET_FLAG(&huart3, UART_FLAG_ORE)     // Overrun Error
                )
    {
      volatile uint32_t dummy = huart3.Instance->DR;
      (void)dummy;

      memset(rxBuffer, 0, sizeof(rxBuffer));

      HAL_UART_DMAStop(&huart3);

      __HAL_UART_CLEAR_FEFLAG(&huart3);
      __HAL_UART_CLEAR_NEFLAG(&huart3);
      __HAL_UART_CLEAR_OREFLAG(&huart3);
      __HAL_UART_CLEAR_PEFLAG(&huart3);
      __HAL_UART_CLEAR_IDLEFLAG(&huart3);

      HAL_UART_DeInit(&huart3);

      MX_USART3_UART_Init();

      HAL_UARTEx_ReceiveToIdle_DMA(&huart3, rxBuffer, sizeof(rxBuffer));

    }
*/
    osDelay(20);
  }
  /* USER CODE END StartDefaultTask */

}

extern uint16_t adcBuffer[];
extern uint8_t adc_ready;

void StartTask02(void *argument)
{
  /* USER CODE BEGIN StartTask02 */
  /* Infinite loop */

  HAL_GPIO_WritePin(UART1_RE_DE_GPIO_Port, UART1_RE_DE_Pin, GPIO_PIN_RESET);

  //HAL_ADC_Start_DMA(&hadc1, (uint32_t*)adcBuffer, ADC_BUF);
  timerStartCreate();

  CircularBuffer10Min buffer10;
  CircularBuffer1Hour buffer1Hour;
  CircularBuffer2Day buffer2Day;

  initBuffer10Min(&buffer10);
  initBuffer1Hour(&buffer1Hour);
  initBuffer2Day(&buffer2Day);

  static uint8_t lasttime = 0;
  static uint8_t lasttime_hour = 0;

  static uint8_t flag_1 = 0; // или bool flag_1 = false;

  //static uint8_t value_was_changed = 1;
  static uint8_t period = 0;

  uint8_t data = 0;

  while (1) {
    //---------------------------------ADC-and-Realay-logic-------------------------

#if DEBUG == 1
    uxHighWaterMark2 = uxTaskGetStackHighWaterMark(NULL);
#endif

    if (adc_ready == 1) {
      //----------------------------------------------------------------------------------WARNING-LOGIC-------------
      if (lasttime != time.minutes) {
        lasttime = time.minutes;
        addValue10Min(&buffer10, REGISTERS[1]);
        if ((time.minutes % 10) == 0) {
          uint16_t Average10min = (uint16_t)getAverage10Min(&buffer10);

          addValue1Hour(&buffer1Hour, Average10min);
          if (lasttime_hour != time.hours) {
            uint16_t Average1h = (uint16_t)getAverage1Hour(&buffer1Hour);
            avg1h = Average1h;
            lasttime_hour = time.hours;
            addValue2Day(&buffer2Day, Average1h);
            avg2d = getAverage2Day(&buffer2Day);
          }
        }
      }
      //----------------------------------------------------------------------------------WARNING-LOGIC-END----------
    }

    if (!start) {
/*
      //warning 2
      if (REGISTERS[1] >= WARNING_VALUE && test_leak == LEAK_TEST_OFF) {
        if (value_was_changed == 1) {
          // set bit 1
          REGISTERS[4] |= (1 << 1);
          data = REGISTERS[1];

          taskENTER_CRITICAL();
          write_to_log(E_WARNING, &data, 1);
          taskEXIT_CRITICAL();

          value_was_changed = 0;
        }
      } else if(REGISTERS[1] < WARNING_VALUE) {
        value_was_changed = 1;
        // reset bit 1
        REGISTERS[4] &= ~(1 << 1);
      }
*/
      if (avg1h) {
        // Если мгновенный ток на 10% выше часового среднего и флаг не выставлен – записываем лог
        if ((REGISTERS[1] > (avg1h * 1.1f)) && (flag_1 == 0)) {
          data = REGISTERS[1];
          taskENTER_CRITICAL();
          write_to_log(E_DELTA_I10, &data, 1);
          flag_1 = 1;
          taskEXIT_CRITICAL();
        }
        // Сброс флага, когда ток снижается ниже среднего
        else if ((REGISTERS[1] <= (avg1h)) && (flag_1 == 1)) {
          flag_1 = 0;
        }
      }
    }

    if ((!(REGISTERS[4] & 0x01)) && (time.days >= 2)) {
      if (avg1h > avg2d) {
        if (period != time.hours) {
          period = time.hours;
          uint16_t delta = (avg2d - avg1h);
          if (delta >= 5) {
            REGISTERS[4] |= 0x01;
            data = 0x02;
            taskENTER_CRITICAL();
            write_to_log(E_WARNING, &data, 1);
            taskEXIT_CRITICAL();
          }
        }
      }
    }

    // OS-UPDATE
    if ((boot_flag_new == 1) && (next_free_addr != 0)) {
      taskENTER_CRITICAL();
      address = SECTOR_8_ADDRESS;
      uint32_t crc_stm = calculate_flash_crc(address, (next_free_addr-4));
      if (crc_os == crc_stm) {
        data = 0x00;
        write_to_log(E_NEW_FW, &data, 1);
        crc_accepted = 1;
        sector_enabled = 2;
        WriteFlash((FlashDataType)0, 0);
        flash_block = 1;
        log_ready = 0;
        startMyTimer_RESET(7000);
        next_free_addr = 0;
      } else if (crc_os != crc_stm) {
        data = 0xFF;
        write_to_log(E_NEW_FW, &data, 1);
        crc_accepted = 0;
        sector_enabled = 2;
        WriteFlash((FlashDataType)0, 0);
        flash_block = 1;
        log_ready = 0;
        next_free_addr = 0;
        startMyTimer_RESET(7000);
      }
      taskEXIT_CRITICAL();
    }

    if (neead_write_flash) {
      osDelay(100);
      WriteFlash((FlashDataType)0, 0);
      neead_write_flash = 0;
    }

    if (restart == 1) {
      startMyTimer_RESET(25000);
      restart = 0;
    }

    if (REGISTERS[4] & TIME_FLAG_APPLY) {
      // Бит TIME_FLAG_APPLY (3-й бит) установлен
      apply_time_from_registers();
    }

    // OS-UPDATE-END
    osDelay(25);
  }
}

typedef enum
{
  STATE_INIT,
  STATE_CREATE_SOCKET,
  STATE_BIND,
  STATE_LISTEN,
  STATE_ACCEPT,
  STATE_RECEIVE,
  STATE_PROCESS,
  STATE_SEND,
  STATE_CLOSE_CONNECTION,
  STATE_ERROR
} FSM_State;

void StartTask03(void *argument)
{
  FSM_State current_state = STATE_INIT;

  volatile err_t res = 0;
  //ip_addr_t local_ip;
  struct netbuf *buf = NULL;
  void *data = NULL;
  uint16_t len = 0;
  uint16_t len_ext = 0;
  uint8_t buffer[20] = {0};
  //local_ip = gnetif.ip_addr;
  err_t bind_result = 0;

  while (!netif_is_link_up(&gnetif)) {
    osDelay(100);
  }

  /* Infinite loop */
  while (1) {

#if DEBUG == 1
    WM_MODBUS = uxTaskGetStackHighWaterMark(NULL);
#endif

    switch ((uint8_t)current_state) {
      case STATE_INIT: {
        nc = netconn_new(NETCONN_TCP);
        if (nc != NULL) {
          current_state = STATE_CREATE_SOCKET;
        } else {
          current_state = STATE_ERROR;
        }
        break;
      }
      //-----------------------------------------------------------------------
      case STATE_CREATE_SOCKET: {
        //local_ip = gnetif.ip_addr;

        if (nc == NULL) {
          current_state = STATE_ERROR;
          break;
          //current_state = STATE_CREATE_SOCKET;
        }

        nc->pcb.tcp->so_options |= SOF_REUSEADDR;

        bind_result = netconn_bind(nc, NULL, 502);

        if (bind_result == ERR_OK) {
          current_state = STATE_LISTEN;
        } else if (bind_result == ERR_USE) {
          CleanupResources(nc, newconn, buf);
          current_state = STATE_INIT;
        } else {
          current_state = STATE_ERROR;
        }
        break;
      }
      //-----------------------------------------------------------------------
      case STATE_LISTEN: {
        if (nc == NULL) {
          current_state = STATE_ERROR;
          break;
          //current_state = STATE_CREATE_SOCKET;
        }
        netconn_listen(nc);
        current_state = STATE_ACCEPT;
        break;
      }
      //-----------------------------------------------------------------------
      case STATE_ACCEPT: {
        if (nc == NULL) {
          //current_state = STATE_CREATE_SOCKET;
          current_state = STATE_ERROR;
          break;
        }
        res = netconn_accept(nc, &newconn);
        if (res == ERR_OK) {
          netconn_set_recvtimeout(newconn, 5000);
          current_state = STATE_RECEIVE;
        } else {
          current_state = STATE_ERROR;
        }
        break;
      }
      //-----------------------------------------------------------------------
      case STATE_RECEIVE: {
        if (newconn == NULL) {
          current_state = STATE_CLOSE_CONNECTION;
          break;
          //current_state = STATE_CREATE_SOCKET;
        }
        res = netconn_recv(newconn, &buf);
        if (res == ERR_OK) {
          netbuf_data(buf, &data, &len);
          memcpy(buffer, data, len);
          current_state = STATE_PROCESS;
        } else {
          if (buf != 0) {
            netbuf_delete(buf);
          }
          current_state = STATE_CLOSE_CONNECTION;
        }
        break;
      }
      //-----------------------------------------------------------------------
      case STATE_PROCESS: {
        modbus(buffer, len, response_data, &len_ext, TCP);
        current_state = STATE_SEND;
        break;
      }
      //-----------------------------------------------------------------------
      case STATE_SEND: {
        if (newconn == NULL) {
          current_state = STATE_ERROR;
          break;
          //current_state = STATE_CREATE_SOCKET;
        }
        send_ethernet(response_data, len_ext, newconn);
        netbuf_delete(buf);
        current_state = STATE_RECEIVE;
        break;
      }
      //-----------------------------------------------------------------------
      case STATE_CLOSE_CONNECTION: {
        if (newconn != NULL) {
          netconn_close(newconn);
          netconn_delete(newconn);
          newconn = NULL;
        }
        netbuf_delete(buf);
        current_state = STATE_ACCEPT;  // Возврат к приёму новых клиентов
        break;
      }
      //-----------------------------------------------------------------------
      case STATE_ERROR: {
        if (nc != NULL) {
          netconn_close(nc);
          netconn_delete(nc);
          nc = NULL;
          newconn = NULL;
        }
        osDelay(10);
        current_state = STATE_INIT;
        break;
      }
    }
  }
}

#define EVENT_RESET 0
#define EVENT_PRESSED 1
#define nBLOCK_BUTTON 0
#define BLOCK_BUTTON 1

void StartTask04(void *argument)
{
  /* Создаём однократный таймер на 1 с */
  xTestBlockTimer = xTimerCreate("TestBlock", pdMS_TO_TICKS(1000), pdFALSE, NULL, vTestBlockReleaseCb);
  configASSERT(xTestBlockTimer);

  start = 0;

  reley_auto_protection = 1;

  uint8_t log_value = 0;

  while (1) {

#if DEBUG == 1
    WM_RELAY = uxTaskGetStackHighWaterMark(NULL);
#endif

    if (mode) {
      switch(REGISTERS[2]) {
        case 0: {
          if (last_position != 0) {
            //HAL_GPIO_WritePin(RELAY_CONTROL_PORT, RELAY_CONTROL_PIN, GPIO_PIN_RESET);
            //HAL_GPIO_WritePin(RELAY_CONTROL_PORT, RELAY_CONTROL_PIN, GPIO_PIN_SET);

#if OUT == 0
            HAL_GPIO_WritePin(RELAY_CONTROL_PORT, RELAY_CONTROL_PIN, GPIO_PIN_SET);
#else
            HAL_GPIO_WritePin(RELAY_CONTROL_PORT, RELAY_CONTROL_PIN, GPIO_PIN_RESET);
#endif

            log_value = 0;
            taskEXIT_CRITICAL();
            write_to_log(E_RELAY_CHANGE_STATE, &log_value, 1);
            taskEXIT_CRITICAL();
            last_position = 0;
          }
          break;
        }

        case 1: {
          if (last_position != 1) {
            //HAL_GPIO_WritePin(RELAY_CONTROL_PORT, RELAY_CONTROL_PIN, GPIO_PIN_SET);
            //HAL_GPIO_WritePin(RELAY_CONTROL_PORT, RELAY_CONTROL_PIN, GPIO_PIN_RESET);

#if OUT == 0
            HAL_GPIO_WritePin(RELAY_CONTROL_PORT, RELAY_CONTROL_PIN, GPIO_PIN_RESET);
#else
            HAL_GPIO_WritePin(RELAY_CONTROL_PORT, RELAY_CONTROL_PIN, GPIO_PIN_SET);
#endif

            last_position = 1;
            log_value = 1;
            taskENTER_CRITICAL();
            write_to_log(E_RELAY_CHANGE_STATE, &log_value, 1);
            taskEXIT_CRITICAL();
          }
          break;
        }
      }
    }

    if ((button_event == EVENT_PRESSED) && (button_block == nBLOCK_BUTTON)) {
      test_leak = LEAK_TEST_ON;
      // start TEST execution
      HAL_GPIO_WritePin(Checking_for_leaks_GPIO_Port, Checking_for_leaks_Pin, GPIO_PIN_SET);
      osDelay(1000);

      if (test_leak == LEAK_TEST_ON) {
        test_leak = LEAK_TEST_OFF;
        HAL_GPIO_WritePin(Checking_for_leaks_GPIO_Port, Checking_for_leaks_Pin, GPIO_PIN_RESET);
        // Logging the TEST event
        log_value = (uint8_t)REGISTERS[1];
        taskENTER_CRITICAL();
        write_to_log(E_TEST, (uint8_t *)&log_value, 1);
        taskEXIT_CRITICAL();
      }

      /* 5. Блокируем повторное нажатие */
      button_event = EVENT_RESET;
      button_block = BLOCK_BUTTON;
      xTimerStart(xTestBlockTimer, 0);
    }
    osDelay(5);
  }
}

void StartTask05(void *argument)
{
  while (1) {
    if (start == 0) {
      OLED_1in5_rgb_run();
    }
    osDelay(10);
  }
}

uint32_t wdi_tick;

void StartTask06(void *argument)
{
  while (1) {
    HAL_GPIO_TogglePin(WDI_GPIO_Port, WDI_Pin);
    osDelay(1000);
#if DEBUG == 1
    wdi_tick++;
    WM_WDI = uxTaskGetStackHighWaterMark(NULL);
#endif
  }
}

/* Private application code */
/* USER CODE BEGIN Application */

//---------------------------------------------------------------------------------HTTPD-SERVER-LOGICS-START---

uint16_t ssi_handler(int iIndex, char *pcInsert, int iInsertLen)
{
  uint8_t buffer[50] = {0};
  uint8_t bufferSize = 50;

  if (iIndex == 0)
  {
    snprintf((char*)buffer, bufferSize, "%02X.%02X.%02X.%02X.%02X.%02X",  gnetif.hwaddr[0], gnetif.hwaddr[1], gnetif.hwaddr[2], gnetif.hwaddr[3], gnetif.hwaddr[4], gnetif.hwaddr[5]);
  }
  else if(iIndex == 1)
  {
    snprintf((char*)buffer, bufferSize, "%d.%d.%d.%d",  IP_ADDRESS[0], IP_ADDRESS[1], IP_ADDRESS[2], IP_ADDRESS[3]);
  }
  else if(iIndex == 2)
  {
    snprintf((char*)buffer, bufferSize, "%d.%d.%d.%d", NETMASK_ADDRESS[0], NETMASK_ADDRESS[1], NETMASK_ADDRESS[2], NETMASK_ADDRESS[3]);
  }
  else if(iIndex == 3)
  {
    snprintf((char*)buffer, bufferSize, "%d.%d.%d.%d", GATEWAY_ADDRESS[0], GATEWAY_ADDRESS[1], GATEWAY_ADDRESS[2], GATEWAY_ADDRESS[3]);
  }
  else if(iIndex == 4)
  {
    snprintf((char*)buffer, bufferSize, "%u", REGISTERS[1]);
  }
  else if(iIndex == 5)
  {
    snprintf((char*)buffer, bufferSize, "%d", time.seconds);
  }
  else if(iIndex == 6)
  {
    snprintf((char*)buffer, bufferSize, "%d", time.minutes);
  }
  else if(iIndex == 7)
  {
    snprintf((char*)buffer, bufferSize, "%d", time.hours);
  }
  else if(iIndex == 8)
  {
    snprintf((char*)buffer, bufferSize, "%d", time.days);
  }
  else if(iIndex == 9)
  {
    snprintf((char*)buffer, bufferSize, "%d", pinaccept);
  }
  else if(iIndex == 10)
  {
    if(REGISTERS[2])
    {
      snprintf((char*)buffer, bufferSize, "РЕЛЕ В СОСТОЯНИИ - ВКЛ");
    }
    else
    {
      snprintf((char*)buffer, bufferSize, "РЕЛЕ В СОСТОЯНИИ - ВЫКЛ");
    }
  }
  else if(iIndex == 11)
  {
    snprintf((char*)buffer, bufferSize, "%d%d%d%d%d%d", SERIAL_ADDRESS[0], SERIAL_ADDRESS[1], SERIAL_ADDRESS[2], SERIAL_ADDRESS[3], SERIAL_ADDRESS[4], SERIAL_ADDRESS[5]);
  }
  else if(iIndex == 12)
  {
    snprintf((char*)buffer, bufferSize, "%d.%d.%d", SOFTWARE_VERSION[0], SOFTWARE_VERSION[1], SOFTWARE_VERSION[2]);
  }
  else if(iIndex == 13)
  {
    if(RS485)
    {
      snprintf((char*)buffer, bufferSize, "Соединение установлено");
    }
    else
    {
      snprintf((char*)buffer, bufferSize, "Соединение разорвано");
    }
  }
  else if(iIndex == 14)
  {
    snprintf((char*)buffer, bufferSize, "%lu", (unsigned long)usart_speed);
  }
  else if(iIndex == 15)
  {
    const char *string = "none";
    const char *string2 = "even";
    const char *string3 = "odd";

    if(strcmp((const char *)uartPARITY, (string)) == 0)
    {
      snprintf((char*)buffer, bufferSize, "%s", string);
    }
    else if(strcmp((const char *)uartPARITY, string2) == 0)
    {
      snprintf((char*)buffer, bufferSize, "%s", string2);
    }
    else if(strcmp((const char *)uartPARITY, string3) == 0)
    {
      snprintf((char*)buffer, bufferSize, "%s", string3);
    }
  }
  else if(iIndex == 16)
  {
    snprintf((char*)buffer, bufferSize, "%d", uartStopBits[0]);
  }
  else if(iIndex == 17)
  {
    snprintf((char*)buffer, bufferSize, "%.9f", (double)C_phase_A);
  }
  else if(iIndex == 18)
  {
    snprintf((char*)buffer, bufferSize, "%.9f", (double)R_leak_A);
  }
  else if(iIndex == 19)
  {
    snprintf((char*)buffer, bufferSize, "%.9f", (double)C_phase_B);
  }
  else if(iIndex == 20)
  {
    snprintf((char*)buffer, bufferSize, "%.9f", (double)R_leak_B);
  }
  else if(iIndex == 21)
  {
    snprintf((char*)buffer, bufferSize, "%.9f", (double)C_phase_C);
  }
  else if(iIndex == 22)
  {
    snprintf((char*)buffer, bufferSize, "%.9f", (double)R_leak_C);
  }
  else if(iIndex == 23)
  {
    snprintf((char*)buffer, bufferSize, "%d", TARGET_VALUE);
  }
  else if(iIndex == 24)
  {
    /*
    if(hw_protection)
    {
    snprintf((char*)buffer, bufferSize, "checked");
  }
    */
    snprintf((char*)buffer, bufferSize, "%d", mode);
  }
  else if(iIndex == 25)
  {
    snprintf((char*)buffer, bufferSize, "%d", crc_accepted);
  }
  else if(iIndex == 26)
  {
    snprintf((char*)buffer, bufferSize, "{\"current\":%u}", REGISTERS[1]);   //like a JSON
  }
  else if(iIndex == 27)
  {
    snprintf((char*)buffer, bufferSize, "%d", WARNING_VALUE);
  }
  else if(iIndex == 28)
  {
    snprintf((char*)buffer, bufferSize, "%d", REGISTERS[4]);
  }
  else if(iIndex == 29)
  {
    log_for_web_init();
    memcpy(pcInsert, (void const *)log_for_wed, 1025);
    return 1025;
  }
  else if(iIndex == 30)
  {
    snprintf((char*)buffer, bufferSize, "%d", relay_timeout);
  }
  else if (iIndex == 31) {
    first_call = 1;          // <-- Сбрасываем тут логи
    pcInsert[0] = '\0';
    return 0;
  }
  else if(iIndex == 32)
  {
    snprintf((char*)buffer, bufferSize, "%u", adc_window_ms);
  }
  else if(iIndex == 33)
  {
    snprintf((char*)buffer, bufferSize, "%u", adc_min_exceed);
  }

  snprintf(pcInsert, iInsertLen, "%s", buffer);
  return strlen(pcInsert);
}

void httpd_ssi_init(void)
{
  http_set_ssi_handler(ssi_handler, ssi_tags, 34);
}

void log_for_web_init()
{
  // Порог пустых записей (0xFF)
  uint8_t FF_THRESHOLD = 5;

  // Статические переменные для отслеживания состояния между вызовами
  // current_addr – текущая позиция чтения (идём в обратном направлении)
  // initial_addr – адрес, с которого начался текущий цикл передачи (для определения полного круга)
  // first_call – флаг первого вызова в рамках одной последовательной передачи логов
  static uint32_t current_addr = 0;
  static uint32_t initial_addr = 0;

  memset((void *)log_for_wed, 0, LOG_BUFF_SIZE);

  int buf_index = 0;
  int max_buf_size = sizeof(log_for_wed);  // Размер выходного буфера (например, 1 КБ)
  int max_entries = max_buf_size / LOG_ENTRY_SIZE; // Количество записей, умещающихся в буфере
  int consecutive_ff = 0; // Счётчик подряд идущих пустых (0xFF) записей

  // При первом вызове начинаем с самой новой записи
  if (first_call)
  {
    if (log_ptr == LOG_START_ADDR_BLOCK)
      // Если указатель равен началу, начинаем с последней валидной записи
      current_addr = LOG_END_ADDR_BLOCK - LOG_ENTRY_SIZE;
    else
      current_addr = log_ptr - LOG_ENTRY_SIZE;
    // Запоминаем стартовую позицию для определения полного круга
    initial_addr = current_addr;
    first_call = 0;
  }

  // Чтение логов в обратном порядке (от самой новой записи)
  for (int i = 0; i < max_entries; i++)
  {
    // Если уже прошли полный круг, прекращаем чтение
    if (i > 0 && current_addr == initial_addr)
      break;

    // Проверка корректности указателя; если он вне диапазона,
    // устанавливаем его на последнюю валидную запись
    if (current_addr < LOG_START_ADDR_BLOCK || current_addr > (LOG_END_ADDR_BLOCK - LOG_ENTRY_SIZE)) {
      current_addr = LOG_END_ADDR_BLOCK - LOG_ENTRY_SIZE;
    }

    uint8_t entry[LOG_ENTRY_SIZE] = {0};
    // Считываем одну запись по текущему адресу

    //Логика для пропуска лишних 8-ми байт в конце каждого сектора (иначе сбивается кратность 12-ти)
    if ((current_addr & 0xDFFFF) == 0xDFFF4)
    {
      current_addr -= 8;
    }
    else if ((current_addr & 0xBFFFF) == 0xBFFF4)
    {
      current_addr -= 8;
    }
    else if ((current_addr & 0x9FFFF) == 0x9FFF4)
    {
      current_addr -= 8;
    }
    else if ((current_addr & 0x7FFFF) == 0x7FFF4)
    {
      current_addr -= 8;
    }
    else if ((current_addr & 0x5FFFF) == 0x5FFF4)
    {
      current_addr -= 8;
    }
    else if ((current_addr & 0x3FFFF) == 0x3FFF4)
    {
      current_addr -= 8;
    }

    memcpy(entry, (const void *)current_addr, LOG_ENTRY_SIZE);

    // Проверяем, является ли запись "пустой" (все байты равны 0xFF)
    int is_ff = 1;
    for (int j = 0; j < LOG_ENTRY_SIZE; j++)
    {
      if (entry[j] != 0xFF)
      {
        is_ff = 0;
        break;
      }
    }

    // Подсчёт подряд идущих пустых записей
    if (is_ff)
      consecutive_ff++;
    else
      consecutive_ff = 0;

    // Если встречено достаточное число пустых записей, считаем, что валидных логов больше нет
    if (consecutive_ff >= FF_THRESHOLD)
      break;

    // Копируем запись в выходной буфер
    memcpy((void *)&log_for_wed[buf_index], entry, LOG_ENTRY_SIZE);
    buf_index += LOG_ENTRY_SIZE;

    // Обновляем указатель. Если вычитание размера записи привело бы к значению ниже начала сектора,
    // переносим указатель на последнюю валидную запись
    if (current_addr - LOG_ENTRY_SIZE < LOG_START_ADDR_BLOCK)
      current_addr = LOG_END_ADDR_BLOCK - LOG_ENTRY_SIZE;
    else
      current_addr -= LOG_ENTRY_SIZE;
  }

  // Если достигнут конец логов (либо по порогу пустых записей, либо полный круг пройден),
  // добавляем сигнальную последовательность в конец выходного буфера
  if (consecutive_ff >= FF_THRESHOLD || ((!first_call) && current_addr == initial_addr) || current_addr == (initial_addr - 1) ||current_addr == (initial_addr - 2) ||current_addr == (initial_addr + 2) ||current_addr == (initial_addr + 1) ||current_addr == (initial_addr + 3) ||current_addr == (initial_addr -3))
  {
    const char marker[] = "\r\n-\r\n";
    int marker_len = sizeof(marker) - 1; // Без завершающего '\0'
    if (buf_index + marker_len < max_buf_size)
    {
      memcpy((void *)&log_for_wed[buf_index], marker, marker_len);
      buf_index += marker_len;
    }
    // Сброс состояния для следующей передачи – в следующий раз начинаем с самой свежей записи
    first_call = 1;
  }
  else if(first_call)
  {
    first_call = 0;
  }
  // Функция используется для SSI (<!--LOG-->),
  // поэтому возвращаем 0

}

//Логика обработки /Save запросов от клиента в веб интерфейсе
const char * SAVE_CGI_Handler(int iIndex, int iNumParams, char *pcParam[], char *pcValue[])
{
  first_call = 1;

  char ip[16] = {0};
  char mask[16] = {0};
  char gateway[16] = {0};
  char mac[18] = {0};
  char serial[18] = {0};
  char rs485speed[18] = {0};
  char rs485paritiy[18] = {0};
  char rs485stopbit[18] = {0};
  char reley_time[16]   = {0};

  char c_phase_a_str[18]  = {0};
  char r_leak_a_str[18]   = {0};
  char c_phase_b_str[18]  = {0};
  char r_leak_b_str[18]   = {0};
  char c_phase_c_str[18]  = {0};
  char r_leak_c_str[18]   = {0};
  char target_value_str[18] = {0};
  char warning_value_str[18] = {0};
  char date_arr[50] = {0};
  char adc_window_str[10] = {0};
  char adc_min_exceed_str[10] = {0};

  uint8_t c_phase_a_flag     = 0;
  uint8_t r_leak_a_flag      = 0;
  uint8_t c_phase_b_flag     = 0;
  uint8_t r_leak_b_flag      = 0;
  uint8_t c_phase_c_flag     = 0;
  uint8_t r_leak_c_flag      = 0;
  uint8_t target_value_flag  = 0;
  uint8_t warning_value_flag = 0;
  uint8_t date_flag          = 0;
  uint8_t reley_time_flag    = 0;
  uint8_t adc_window_flag    = 0;
  uint8_t adc_min_exceed_flag = 0;

  uint8_t ip_flag = 0;
  uint8_t mask_flag = 0;
  uint8_t gateway_flag = 0;
  uint8_t mac_flag = 0;
  uint8_t pinget = 0;
  uint8_t serial_flag = 0;
  uint8_t speed_flag = 0;
  uint8_t paritiy_flag = 0;
  uint8_t stopbit_flag = 0;

  for (int i = 0; i < iNumParams; i++)
  {
    if (strcmp(pcParam[i], "ip") == 0)
    {
      strncpy(ip, pcValue[i], sizeof(ip) - 1);
      ip_flag = 1;
    }
    else if (strcmp(pcParam[i], "mask") == 0)
    {
      strncpy(mask, pcValue[i], sizeof(mask) - 1);
      mask_flag = 1;
    }
    else if (strcmp(pcParam[i], "gateway") == 0)
    {
      strncpy(gateway, pcValue[i], sizeof(gateway) - 1);
      gateway_flag = 1;
    }
    else if (strcmp(pcParam[i], "mac") == 0)
    {
      strncpy(mac, pcValue[i], sizeof(mac) - 1);
      mac_flag = 1;
    }
    else if(strcmp(pcParam[i], "pin") == 0)
    {
      strncpy(mac, pcValue[i], sizeof(mac) - 1);
      for (int i = 0; i < 6; i++)
      {
        if(mac[i] == PIN[i])
        {
          pinget++;
        }
      }
      if (pinget == 6)
      {
        pinaccept = 1;
      }
      memset(mac, 0, sizeof(mac));
    }
    else if (strcmp(pcParam[i], "relay") == 0)
    {
      if(REGISTERS[2])
      {
        REGISTERS[2] = 0;
      }
      else
      {
        REGISTERS[2] = 1;
      }
    }
    if (strcmp(pcParam[i], "serial") == 0)
    {
      strncpy(serial, pcValue[i], sizeof(serial) - 1);
      serial_flag = 1;
    }
    else if (strcmp(pcParam[i], "rs485speed") == 0)
    {
      strncpy(rs485speed, pcValue[i], sizeof(rs485speed) - 1);
      speed_flag = 1;
    }
    else if (strcmp(pcParam[i], "rs485parity") == 0)
    {
      strncpy(rs485paritiy, pcValue[i], sizeof(rs485paritiy) - 1);
      paritiy_flag = 1;
    }
    else if (strcmp(pcParam[i], "rs485stopbit") == 0)
    {
      strncpy(rs485stopbit, pcValue[i], sizeof(rs485stopbit) - 1);
      stopbit_flag = 1;
    }
    else if (strcmp(pcParam[i], "c_phase_a") == 0)
    {
      strncpy(c_phase_a_str, pcValue[i], sizeof(c_phase_a_str) - 1);
      c_phase_a_flag = 1;
    }
    else if (strcmp(pcParam[i], "r_leak_a") == 0)
    {
      strncpy(r_leak_a_str, pcValue[i], sizeof(r_leak_a_str) - 1);
      r_leak_a_flag = 1;
    }
    else if (strcmp(pcParam[i], "c_phase_b") == 0)
    {
      strncpy(c_phase_b_str, pcValue[i], sizeof(c_phase_b_str) - 1);
      c_phase_b_flag = 1;
    }
    else if (strcmp(pcParam[i], "r_leak_b") == 0)
    {
      strncpy(r_leak_b_str, pcValue[i], sizeof(r_leak_b_str) - 1);
      r_leak_b_flag = 1;
    }
    else if (strcmp(pcParam[i], "c_phase_c") == 0)
    {
      strncpy(c_phase_c_str, pcValue[i], sizeof(c_phase_c_str) - 1);
      c_phase_c_flag = 1;
    }
    else if (strcmp(pcParam[i], "r_leak_c") == 0)
    {
      strncpy(r_leak_c_str, pcValue[i], sizeof(r_leak_c_str) - 1);
      r_leak_c_flag = 1;
    }
    else if (strcmp(pcParam[i], "target_value") == 0)
    {
      strncpy(target_value_str, pcValue[i], sizeof(target_value_str) - 1);
      target_value_flag = 1;
    }
    else if (strcmp(pcParam[i], "warning_value") == 0)
    {
      strncpy(warning_value_str, pcValue[i], sizeof(warning_value_str) - 1);
      warning_value_flag = 1;
    }
    else if(strcmp(pcParam[i], "test") == 0)
    {
      button_event = 1;
    }
    else if(strcmp(pcParam[i], "date") == 0)
    {
      strncpy(date_arr, pcValue[i], sizeof(date_arr) - 1);
      date_flag = 1;
    }
    else if (strcmp(pcParam[i], "givetime") == 0)
    {
      uint16_t mask = (1 << 2);
      REGISTERS[4] = (REGISTERS[4] | mask);
    }
    else if (strcmp(pcParam[i], "swichmode") == 0)
    {
      REGISTERS[4] ^= (1 << 4);

      if(mode)
      {
        mode = 0;
      }
      else
      {
        mode = 1;
      }
    }
    else if (strcmp(pcParam[i], "reley_time") == 0)
    {
      strncpy(reley_time, pcValue[i], sizeof(reley_time) - 1);
      reley_time_flag = 1;
    }
    else if (strcmp(pcParam[i], "adc_window") == 0)
    {
      strncpy(adc_window_str, pcValue[i], sizeof(adc_window_str) - 1);
      adc_window_flag = 1;
    }
    else if (strcmp(pcParam[i], "adc_min_exceed") == 0)
    {
      strncpy(adc_min_exceed_str, pcValue[i], sizeof(adc_min_exceed_str) - 1);
      adc_min_exceed_flag = 1;
    }
  }

  if (date_flag != 0)
  {
    taskENTER_CRITICAL();
    save_time_to_rtc((uint8_t*) date_arr);
    date_flag = 0;
    taskEXIT_CRITICAL();
  }

  if(mac_flag != 0)
  {
    convert_str_to_uint8_array(mac, output, 1);
    taskENTER_CRITICAL();
    WriteFlash(MAC, output);
    memset(output, 0, sizeof(output));
    mac_flag = 0;
    ReadFlash(MAC, gnetif.hwaddr);
    restart = 1;
    pinaccept = 1;
    taskEXIT_CRITICAL();
  }

  if(serial_flag != 0)
  {
    convert_str_to_uint8_array_serial(serial, output);
    taskENTER_CRITICAL();
    WriteFlash(SERIAL, output);
    memset(output, 0, sizeof(output));
    mask_flag = 0;
    ReadFlash(SERIAL, SERIAL_ADDRESS);
    restart = 1;
    pinaccept = 1;
    taskEXIT_CRITICAL();
  }

  if (c_phase_a_flag != 0)
  {
    convert_str_to_float_bytes(c_phase_a_str, output);
    taskENTER_CRITICAL();
    WriteFlash(C_PHASE_A, output);
    memset(output, 0, sizeof(output));
    c_phase_a_flag = 0;
    C_phase_A = *((float *)FLASH_ADDRESS_C_PHASE_A);
    write_to_log(E_C_PHASE_A, (uint8_t *)&C_phase_A, sizeof(C_phase_A));
    taskEXIT_CRITICAL();
  }

  if (r_leak_a_flag != 0)
  {
    convert_str_to_float_bytes(r_leak_a_str, output);
    taskENTER_CRITICAL();
    WriteFlash(R_LEAK_A, output);
    memset(output, 0, sizeof(output));
    r_leak_a_flag = 0;
    R_leak_A  = *((float *)FLASH_ADDRESS_R_LEAK_A);
    write_to_log(E_R_LEAK_A, (uint8_t *)&R_leak_A, sizeof(R_leak_A));
    taskEXIT_CRITICAL();
  }

  if (c_phase_b_flag != 0)
  {
    taskENTER_CRITICAL();
    convert_str_to_float_bytes(c_phase_b_str, output);
    WriteFlash(C_PHASE_B, output);
    memset(output, 0, sizeof(output));
    c_phase_b_flag = 0;
    C_phase_B = *((float *)FLASH_ADDRESS_C_PHASE_B);
    write_to_log(E_C_PHASE_B, (uint8_t *)&C_phase_B, sizeof(C_phase_B));
    taskEXIT_CRITICAL();
  }

  if (r_leak_b_flag != 0)
  {
    taskENTER_CRITICAL();
    convert_str_to_float_bytes(r_leak_b_str, output);
    WriteFlash(R_LEAK_B, output);
    memset(output, 0, sizeof(output));
    r_leak_b_flag = 0;
    R_leak_B  = *((float *)FLASH_ADDRESS_R_LEAK_B);
    write_to_log(E_R_LEAK_B, (uint8_t *)&R_leak_B, sizeof(R_leak_B));
    taskEXIT_CRITICAL();
  }

  if (c_phase_c_flag != 0)
  {
    taskENTER_CRITICAL();
    convert_str_to_float_bytes(c_phase_c_str, output);
    WriteFlash(C_PHASE_C, output);
    memset(output, 0, sizeof(output));
    c_phase_c_flag = 0;
    C_phase_C = *((float *)FLASH_ADDRESS_C_PHASE_C);
    write_to_log(E_C_PHASE_C, (uint8_t *)&C_phase_C, sizeof(C_phase_C));
    taskEXIT_CRITICAL();
  }

  if (r_leak_c_flag != 0)
  {
    taskENTER_CRITICAL();
    convert_str_to_float_bytes(r_leak_c_str, output);
    WriteFlash(R_LEAK_C, output);
    memset(output, 0, sizeof(output));
    r_leak_c_flag = 0;
    R_leak_C  = *((float *)FLASH_ADDRESS_R_LEAK_C);
    write_to_log(E_R_LEAK_C, (uint8_t *)&R_leak_C, sizeof(R_leak_C));
    taskEXIT_CRITICAL();
  }

  if (target_value_flag != 0)
  {
    taskENTER_CRITICAL();
    output[0] = (uint8_t)atoi(target_value_str);
    WriteFlash(TaRGET_VALUE, output);
    memset(output, 0, sizeof(output));
    target_value_flag = 0;
    TARGET_VALUE = *((uint8_t *)FLASH_ADDRESS_TARGET_VALUE);

    write_to_log(E_TARGET_VALUE, &TARGET_VALUE, 1);
    taskEXIT_CRITICAL();
  }

  if (warning_value_flag != 0)
  {
    taskENTER_CRITICAL();
    output[0] = (uint8_t)atoi(warning_value_str);
    WriteFlash(Warning_VALUE, output);
    memset(output, 0, sizeof(output));
    warning_value_flag = 0;
    WARNING_VALUE = *((uint8_t *)FLASH_ADDRESS_WARNING_VALUE);

    write_to_log(E_WARNING_VALUE, &WARNING_VALUE, 1);
    taskEXIT_CRITICAL();
  }

  if(reley_time_flag != 0)
  {
    taskENTER_CRITICAL();

    uint16_t value = (uint16_t)atoi(reley_time);   // value = 300
    memcpy(output, &value, sizeof(value));

    WriteFlash(Relay_TIME, output);
    memset(output, 0, sizeof(output));
    reley_time_flag = 0;
    relay_timeout = *((uint16_t *)FLASH_ADDRESS_RELAY_TIME);

    //write_to_log(0x18, (uint8_t *)&relay_timeout, 1);
    taskEXIT_CRITICAL();
  }

  if (adc_window_flag != 0)
  {
    taskENTER_CRITICAL();
    uint16_t value = (uint16_t)atoi(adc_window_str);

    if (value < 10) value = 10;
    if (value > 80) value = 80;

    memcpy(output, &value, sizeof(value));

    WriteFlash(ADC_WINDOW, output);
    memset(output, 0, sizeof(output));
    adc_window_flag = 0;
    adc_window_ms = *((uint16_t *)FLASH_ADDRESS_ADC_WINDOW);
    taskEXIT_CRITICAL();
  }

  if (adc_min_exceed_flag != 0)
  {
    taskENTER_CRITICAL();
    output[0] = (uint8_t)atoi(adc_min_exceed_str);

    if (output[0] > 4) output[0] = 4;

    WriteFlash(ADC_MIN_EXCEED, output);
    memset(output, 0, sizeof(output));
    adc_min_exceed_flag = 0;
    adc_min_exceed = *((uint8_t *)FLASH_ADDRESS_ADC_MIN_EXCEED);
    taskEXIT_CRITICAL();
  }

  if (pinaccept) {
    taskENTER_CRITICAL();
    if (ip_flag != 0)
    {
      convert_str_to_uint8_array(ip, output, 0);
      WriteFlash(IP, output);
      memset(output, 0, sizeof(output));
      ip_flag = 0;
      ReadFlash(IP, IP_ADDRESS);

      write_to_log(E_IP_ADDR, IP_ADDRESS, 4);
    }
    if(mask_flag != 0)
    {
      convert_str_to_uint8_array(mask, output, 0);
      WriteFlash(NETMASK, output);
      memset(output, 0, sizeof(output));
      mask_flag = 0;
      ReadFlash(NETMASK, NETMASK_ADDRESS);

      write_to_log(E_NETMASK, NETMASK_ADDRESS, 4);
    }
    if(gateway_flag != 0)
    {
      convert_str_to_uint8_array(gateway, output, 0);
      WriteFlash(GATEWAY, output);
      memset(output, 0, sizeof(output));
      gateway_flag = 0;
      ReadFlash(GATEWAY, GATEWAY_ADDRESS);

      write_to_log(E_GATEWAY, GATEWAY_ADDRESS, 4);
    }
    if(speed_flag != 0)
    {
      memcpy(output, rs485speed, sizeof(rs485speed));
      WriteFlash(RS485SPEED, output);
      memset(output, 0, sizeof(output));
      speed_flag = 0;
      ReadFlash(RS485SPEED, USART_3_SPEED);

      write_to_log(E_USART_SPEED, USART_3_SPEED, 4);
    }
    if(paritiy_flag != 0)
    {
      WriteFlash(RS485PARITIY, (uint8_t*)rs485paritiy);
      memset(output, 0, sizeof(output));
      paritiy_flag = 0;
      ReadFlash(RS485PARITIY, (uint8_t*)uartPARITY);

      write_to_log(E_USART_PARITIY, (uint8_t*)uartPARITY, 4);
    }
    if(stopbit_flag != 0)
    {
      convert_str_to_uint8_array(rs485stopbit, output, 2);
      WriteFlash(RS485STOPBIT, output);
      memset(output, 0, sizeof(output));
      stopbit_flag = 0;
      ReadFlash(RS485STOPBIT, uartStopBits);

      write_to_log(E_USART_STOPBIT, uartStopBits, 1);
    }

    taskEXIT_CRITICAL();
    restart = 1;

    return 0;
  }
  return 0;
}

const char * JSON_CGI_Handler(int iIndex, int iNumParams, char *pcParam[], char *pcValue[])
{
  //first_call = 1;

  return 0; //там просто подставить SSI тег текущего тока
}

uint8_t loghhh = 0;

const char * LOG_CGI_Handler(int iIndex, int iNumParams, char *pcParam[], char *pcValue[])
{
    return 0;
}
//---------------------------------------------------------------------------------HTTPD-SERVER-LOGICS-END---

//---------------------------------------------------------------------------------FLASH-LOGICS-START--------

void ReadFlash(FlashDataType type, uint8_t* buffer)
{
  uint32_t address = FLASH_ADDRESS_MAC;
  uint32_t dataSize = 0;

  switch (type)
  {
  case MAC:
    address = FLASH_ADDRESS_MAC;
    dataSize = 6;
    break;
  case IP:
    address = FLASH_ADDRESS_IP;
    dataSize = 4;
    break;
  case NETMASK:
    address = FLASH_ADDRESS_NETMASK;
    dataSize = 4;
    break;
  case GATEWAY:
    address = FLASH_ADDRESS_GATEWAY;
    dataSize = 4;
    break;
  case SERIAL:
    address = FLASH_ADDRESS_SERIAL;
    dataSize = 6;
    break;
  case RS485SPEED:
    address = FLASH_ADDRESS_RS485_SPEED;
    dataSize = 10;
    break;
  case RS485PARITIY:
    address = FLASH_ADDRESS_RS485_PARITIY;
    dataSize = 10;
    break;
  case RS485STOPBIT:
    address = FLASH_ADDRESS_RS485_STOPBIT;
    dataSize = 10;
    break;
  case Relay_TIME:
    address = FLASH_ADDRESS_RELAY_TIME;
    dataSize = 4;
  default:
    return;
  }

  for (uint32_t i = 0; i < dataSize; i++)
  {
    buffer[i] = *(uint8_t*)(address + i);
  }
}

//Удаляет лишние знаки из строки (АА:FF:SS:DD:HH -> AAFFSSDDHH)
void convert_str_to_uint8_array(const char* input, uint8_t* output, int is_mac)
{
  int i = 0;
  if (is_mac == 1)
  {
    while (*input)
    {
      if (*input != ',' && *input != '.' && *input != ':' && *input != '-')
      {
        char hex[3] = {input[0], input[1], '\0'};
        output[i++] = (uint8_t) strtol(hex, NULL, 16);
        input += 2;
      }
      else
      {
        input++;
      }
    }
  }
  else if(is_mac == 2)
  {
    int i = 0;
    while(input[i])
    {
      if (input[i] >= '0' && input[i] <= '9')
      {
        output[i] = input[i] - '0';
        i++;
      }
      else
      {
        output[i] = 0;
        i++;
      }
    }
  }
  else
  {
    while (*input)
    {
      if (*input != '.' && *input != ':' && *input != '-')
      {
        output[i++] = (uint8_t) strtol(input, (char **) &input, 10);
      }
      else
      {
        input++;
      }
    }
  }
}

void convert_str_to_float_bytes(const char* input, uint8_t* output)
{
    // Преобразуем строку в float
    float value = atof(input);

    // Копируем байты float в массив output
    memcpy(output, &value, sizeof(float));
}

void convert_str_to_uint8_array_serial(const char* input, uint8_t* output)
{
  for (int i = 0; i < 6; i++)
  {
    output[i] = input[i] - '0';
  }
}

__attribute__((section(".ramfunc")))
void WriteToFlash(uint32_t startAddress, uint8_t* data, uint32_t length)
{
  if (!flash_block) {
    uint32_t sector_error = 0;
    FLASH_EraseInitTypeDef FLASH_EraseInitStruct;
    FLASH_EraseInitStruct.TypeErase = FLASH_TYPEERASE_SECTORS;
    FLASH_EraseInitStruct.NbSectors = 1;
    FLASH_EraseInitStruct.VoltageRange = FLASH_VOLTAGE_RANGE_3;

    __HAL_FLASH_CLEAR_FLAG(FLASH_FLAG_EOP|FLASH_FLAG_OPERR|FLASH_FLAG_WRPERR|
                           FLASH_FLAG_PGAERR|FLASH_FLAG_PGPERR|FLASH_FLAG_PGSERR);

    __disable_irq();

    HAL_FLASH_Unlock();

    if((startAddress >= 0x0800C000) && (startAddress <= 0x0800FFFF))
    {
      FLASH_EraseInitStruct.Sector = FLASH_SECTOR_3;
      HAL_FLASHEx_Erase(&FLASH_EraseInitStruct, &sector_error);
      //FLASH_Erase_Sector(FLASH_SECTOR_3, VOLTAGE_RANGE_3);
    }
    else if((startAddress >= 0x08100000) && (startAddress <= 0x08103FFF))
    {
      FLASH_EraseInitStruct.Sector = FLASH_SECTOR_12;
      HAL_FLASHEx_Erase(&FLASH_EraseInitStruct, &sector_error);
      //FLASH_Erase_Sector(FLASH_SECTOR_12, VOLTAGE_RANGE_3);
    }

    for (uint32_t i = 0; i < length; i++) {
      if (HAL_FLASH_Program(FLASH_TYPEPROGRAM_BYTE, startAddress + i, data[i]) != HAL_OK) {
        HAL_FLASH_Lock();
        __enable_irq();
        return;
      }
    }

    HAL_FLASH_Lock();

    __enable_irq();
  }
}

// Функция для работы с переменными в памяти
__attribute__((section(".ramfunc")))
void WriteFlash(FlashDataType type, uint8_t* data)
{
  size_t minFreeHeapSize = xPortGetMinimumEverFreeHeapSize();
  taskENTER_CRITICAL();
  uint8_t sectorData[0x1000]; // Формат сектора памяти (4 KB)
  uint32_t *address = 0;
  uint32_t dataSize = 0;

  // Считывание полного сектора
  for (uint32_t i = 0; i < 0x1000; i++) {
    sectorData[i] = *(volatile uint8_t*)(0x0800C000 + i);
  }

  // Изменение значений в буфере
  sectorData[BOOT_OS_OK_ADDRESS - 0x0800C000] = boot_os_ok;
  //sectorData[BOOT_FLAG_CRC_ADDRESS - 0x0800C000] = boot_flag_crc;
  sectorData[BOOT_FLAG_NEW_ADDRESS - 0x0800C000] = boot_flag_new;
  sectorData[SECTOR_ENABLED_ADDRESS - 0x0800C000] = sector_enabled;
  sectorData[LOG_SECTOR_ACTIVE - 0x0800C000] = log_sector_active;

  uint32_t index = BOOT_CRC_ADDRESS - 0x0800C000;

  sectorData[index + 0] = (uint8_t)(crc_os & 0xFF);        // младший байт
  sectorData[index + 1] = (uint8_t)((crc_os >> 8) & 0xFF);  // второй байт
  sectorData[index + 2] = (uint8_t)((crc_os >> 16) & 0xFF); // третий байт
  sectorData[index + 3] = (uint8_t)((crc_os >> 24) & 0xFF); // старший байт

  switch (type) {
    case MAC: {
      address = (uint32_t *)FLASH_ADDRESS_MAC;
      dataSize = 6;
      break;
    }
    case IP: {
      address = (uint32_t *)FLASH_ADDRESS_IP;
      dataSize = 4;
      break;
    }
    case NETMASK: {
      address = (uint32_t *)FLASH_ADDRESS_NETMASK;
      dataSize = 4;
      break;
    }
    case GATEWAY: {
      address = (uint32_t *)FLASH_ADDRESS_GATEWAY;
      dataSize = 4;
      break;
    }
    case SERIAL: {
      address = (uint32_t *)FLASH_ADDRESS_SERIAL;
      dataSize = 6;
      break;
    }
    case RS485SPEED: {
      address = (uint32_t *)FLASH_ADDRESS_RS485_SPEED;
      dataSize = 10;
      break;
    }
    case RS485PARITIY: {
      address = (uint32_t *)FLASH_ADDRESS_RS485_PARITIY;
      dataSize = 10;
      break;
    }
    case RS485STOPBIT: {
      address = (uint32_t *)FLASH_ADDRESS_RS485_STOPBIT;
      dataSize = 1;
      break;
    }
    case C_PHASE_A: {
      address = (uint32_t *)FLASH_ADDRESS_C_PHASE_A;
      dataSize = 4;
      break;
    }
    case R_LEAK_A: {
      address = (uint32_t *)FLASH_ADDRESS_R_LEAK_A;
      dataSize = 4;
      break;
    }
    case C_PHASE_B: {
      address = (uint32_t *)FLASH_ADDRESS_C_PHASE_B;
      dataSize = 4;
      break;
    }
    case R_LEAK_B: {
      address = (uint32_t *)FLASH_ADDRESS_R_LEAK_B;
      dataSize = 4;
      break;
    }
    case C_PHASE_C: {
      address = (uint32_t *)FLASH_ADDRESS_C_PHASE_C;
      dataSize = 4;
      break;
    }
    case R_LEAK_C: {
      address = (uint32_t *)FLASH_ADDRESS_R_LEAK_C;
      dataSize = 4;
      break;
    }
    case TaRGET_VALUE: {
      address = (uint32_t *)FLASH_ADDRESS_TARGET_VALUE;
      dataSize = 1;
      break;
    }
    case HW_PROTECTION: {
      address = (uint32_t *)FLASH_ADDRESS_HW_PROTECTION;
      dataSize = 1;
      break;
    }
    case Warning_VALUE:{
      address = (uint32_t *)FLASH_ADDRESS_WARNING_VALUE;
      dataSize = 1;
      break;
    }
    case Relay_TIME:{
      address = (uint32_t *)FLASH_ADDRESS_RELAY_TIME;
      dataSize = 4;
      break;
    }
    case ADC_WINDOW:{
      address = (uint32_t *)FLASH_ADDRESS_ADC_WINDOW;
      dataSize = 2;
      break;
    }
    case ADC_MIN_EXCEED:{
      address = (uint32_t *)FLASH_ADDRESS_ADC_MIN_EXCEED;
      dataSize = 1;
      break;
    }
    default: {
      taskEXIT_CRITICAL();
      return;
    }
  }

  if (data) {
    memcpy(&sectorData[(uint32_t)address - 0x0800C000], data, dataSize);
  }

  //osDelay(150);
  // Запись полного сектора в память
  WriteToFlash(0x0800C000, sectorData, 0x1000);
  taskEXIT_CRITICAL();
}

void load_values_from_flash(void)
{
  uint32_t temp;
  uint16_t temp16;
  uint8_t temp8;

  // Чтение и проверка C_phase_A
  temp = *(volatile uint32_t *)FLASH_ADDRESS_C_PHASE_A;
  if (temp != 0xFFFFFFFF) {
    memcpy(&C_phase_A, &temp, sizeof(float));
  } else {
    //C_phase_A = 0.3f;
    C_phase_A = 0.2f;
  }

  // Чтение и проверка R_leak_A
  temp = *(volatile uint32_t *)FLASH_ADDRESS_R_LEAK_A;
  if (temp != 0xFFFFFFFF) {
    memcpy(&R_leak_A, &temp, sizeof(float));
  } else {
    R_leak_A = 10.0f;
  }

  // Чтение и проверка C_phase_B
  temp = *(volatile uint32_t *)FLASH_ADDRESS_C_PHASE_B;
  if (temp != 0xFFFFFFFF) {
    memcpy(&C_phase_B, &temp, sizeof(float));
  } else {
    //C_phase_B = 0.3f;
    C_phase_B = 0.2f;
  }

  // Чтение и проверка R_leak_B
  temp = *(volatile uint32_t *)FLASH_ADDRESS_R_LEAK_B;
  if (temp != 0xFFFFFFFF) {
    memcpy(&R_leak_B, &temp, sizeof(float));
  } else {
    R_leak_B = 10.0f;
  }

  // Чтение и проверка C_phase_C
  temp = *(volatile uint32_t *)FLASH_ADDRESS_C_PHASE_C;
  if (temp != 0xFFFFFFFF) {
    memcpy(&C_phase_C, &temp, sizeof(float));
  } else {
    //C_phase_C = 0.3f;
    C_phase_C = 0.2f;
  }

  // Чтение и проверка R_leak_C
  temp = *(volatile uint32_t *)FLASH_ADDRESS_R_LEAK_C;
  if (temp != 0xFFFFFFFF) {
    memcpy(&R_leak_C, &temp, sizeof(float));
  } else {
    R_leak_C = 10.0f;
  }

  // Чтение и проверка TARGET_VALUE
  TARGET_VALUE = *(volatile uint8_t *)FLASH_ADDRESS_TARGET_VALUE;
  if (TARGET_VALUE == 0xFF) {
    TARGET_VALUE = TARGET_VALUE_DEF;
  }

  /*
  hw_protection = *(volatile uint8_t *)FLASH_ADDRESS_HW_PROTECTION;
  if (hw_protection == 0xFF) {
  hw_protection = 1;
}
  */

  WARNING_VALUE = *(volatile uint8_t *)FLASH_ADDRESS_WARNING_VALUE;
  if(WARNING_VALUE == 0xFF) {
    WARNING_VALUE = WARNING_VALUE_DEF;
  }

  relay_timeout = *(volatile uint16_t *)FLASH_ADDRESS_RELAY_TIME;
  if (relay_timeout == 0xFFFF)
  {
    relay_timeout = 250;
  }

  temp16 = *(volatile uint16_t *)FLASH_ADDRESS_ADC_WINDOW;
  if (temp16 != 0xFFFF)
  {
    adc_window_ms = temp16;
  }
  else
  {
    adc_window_ms = adc_window_ms_def;
  }

  temp8 = *(volatile uint8_t *)FLASH_ADDRESS_ADC_MIN_EXCEED;
  if (temp8 != 0xFF)
  {
    adc_min_exceed = temp8;
  }
  else
  {
    adc_min_exceed = adc_min_exceed_def;
  }
}

//---------------------------------------------------------------------------------FLASH-LOGICS-END--------

//---------------------------------------------------------------------------------MOODBUS-OUTPUT-START----
//функция для отправки ответа modbus TCP
void send_ethernet(uint8_t *data, uint16_t len, struct netconn *newconn)
{
  struct netbuf *response_buf = netbuf_new();

  netbuf_ref(response_buf, data, len);
  if (newconn != NULL && netconn_err(newconn) == ERR_OK) {
    err_t xRes = netconn_write(newconn, data, len, NETCONN_COPY);

  }
  netbuf_delete(response_buf);
}

//функция вызывается когда передача по usart завершена
void HAL_UART_TxCpltCallback(UART_HandleTypeDef *huart)
{
  HAL_GPIO_WritePin(UART1_RE_DE_GPIO_Port, UART1_RE_DE_Pin, GPIO_PIN_RESET);
  HAL_UARTEx_ReceiveToIdle_DMA(&huart3, rxBuffer, sizeof(rxBuffer));
}

//функция для отправки ответа modbus RTU
void send_uart(const uint8_t *response, uint16_t len)
{
  HAL_GPIO_WritePin(UART1_RE_DE_GPIO_Port, UART1_RE_DE_Pin, GPIO_PIN_SET);
  HAL_StatusTypeDef ui;
  ui = HAL_UART_Transmit_DMA(&huart3, response, len);
  if (ui != HAL_OK) {
    HAL_UART_ErrorCallback(&huart3);
  }
}

//функция для очистки флагов usart и его последующего перезапуска
//(необходима для ситуаций, когда к usart подклются на неверной скорости)
void HAL_UART_ErrorCallback(UART_HandleTypeDef *huart)
{
  if (huart->Instance == USART3) {
    HAL_GPIO_WritePin(UART1_RE_DE_GPIO_Port, UART1_RE_DE_Pin, GPIO_PIN_RESET);
    while (HAL_UARTEx_ReceiveToIdle_DMA(huart, rxBuffer, sizeof(rxBuffer)) != HAL_OK)
    {
      HAL_UART_DMAStop(huart);
    }
    // we don't need half-transfer interrupt
    __HAL_DMA_DISABLE_IT(huart->hdmarx, DMA_IT_HT);
  }

/*
  HAL_GPIO_WritePin(UART1_RE_DE_GPIO_Port, UART1_RE_DE_Pin, GPIO_PIN_SET);

  osDelay(100);

  if (huart == &huart3)
  {
    uint32_t er = HAL_UART_GetError(&huart3);

    if (er & HAL_UART_ERROR_PE)
    {
      __HAL_UART_CLEAR_PEFLAG(&huart3);
    }
    if (er & HAL_UART_ERROR_NE)
    {
      __HAL_UART_CLEAR_NEFLAG(&huart3);
    }
    if (er & HAL_UART_ERROR_FE)
    {
      __HAL_UART_CLEAR_FEFLAG(&huart3);
    }
    if (er & HAL_UART_ERROR_ORE)
    {
      __HAL_UART_CLEAR_OREFLAG(&huart3);
    }
    if (er & HAL_UART_ERROR_DMA)
    {
      __HAL_UART_CLEAR_NEFLAG(&huart3);
    }

    huart->ErrorCode = HAL_UART_ERROR_NONE;
    er = HAL_UARTEx_ReceiveToIdle_DMA(huart, rxBuffer, sizeof(rxBuffer));
    osDelay(100);
    HAL_GPIO_WritePin(UART1_RE_DE_GPIO_Port, UART1_RE_DE_Pin, GPIO_PIN_RESET);
  }

      if (
        __HAL_UART_GET_FLAG(&huart3, UART_FLAG_FE)  ||  // Frame Error
          __HAL_UART_GET_FLAG(&huart3, UART_FLAG_NE)  ||  // Noise Error
            __HAL_UART_GET_FLAG(&huart3, UART_FLAG_PE)  ||  // Parity Error
              __HAL_UART_GET_FLAG(&huart3, UART_FLAG_ORE)     // Overrun Error
                )
    {
      volatile uint32_t dummy = huart3.Instance->DR;
      (void)dummy;

      memset(rxBuffer, 0, sizeof(rxBuffer));

      HAL_UART_DMAStop(&huart3);

      __HAL_UART_CLEAR_FEFLAG(&huart3);
      __HAL_UART_CLEAR_NEFLAG(&huart3);
      __HAL_UART_CLEAR_OREFLAG(&huart3);
      __HAL_UART_CLEAR_PEFLAG(&huart3);
      __HAL_UART_CLEAR_IDLEFLAG(&huart3);

      HAL_UART_DeInit(&huart3);

      MX_USART3_UART_Init();

      HAL_UARTEx_ReceiveToIdle_DMA(&huart3, rxBuffer, sizeof(rxBuffer));

    }
*/
}

//---------------------------------------------------------------------------------MOODBUS-OUTPUT-END----

//---------------------------------------------------------------------------------ADC-LOGICS-START----

//---------------------------------------------------------------------------------ANOTHER-CODE-START---

//Таймер, который срабатывает если пользователь изменил настройки
//в веб интерфейсе и необходима перезагрузка для их применения
void startMyTimer_RESET(uint32_t timeout_ms)
{
  TimerHandle_t myTimer = xTimerCreate("OneShotTimer", pdMS_TO_TICKS(timeout_ms), pdFALSE, (void *) 0, vMyTimerCallback);

  if (myTimer != NULL) {
    xTimerStart(myTimer, 0);
  } else {
    while(1);
  }
}

void vMyTimerCallback(TimerHandle_t xTimer)
{
  HAL_NVIC_SystemReset();
}

char stackOverflowTaskName[64];

// Переполнение стека
void vApplicationStackOverflowHook(TaskHandle_t xTask, char *pcTaskName)
{
  strncpy(stackOverflowTaskName, pcTaskName, 64 - 1);
  stackOverflowTaskName[64 - 1] = '\0';
  uint16_t TTT = 0;

  while(1)
  {
    TTT++;  //FREERTOS STACK ERROR
  }
}

//прерывание с кнопки PA12
void EXTI12_Init(void)
{
  __HAL_RCC_SYSCFG_CLK_ENABLE();

  SYSCFG->EXTICR[3] &= ~(SYSCFG_EXTICR4_EXTI12);
  SYSCFG->EXTICR[3] |= (SYSCFG_EXTICR4_EXTI12_PA);

  EXTI->IMR |= EXTI_IMR_MR12;

  EXTI->RTSR |= EXTI_RTSR_TR12;
  EXTI->FTSR &= ~EXTI_FTSR_TR12;

  NVIC_EnableIRQ(EXTI15_10_IRQn);
  NVIC_SetPriority(EXTI15_10_IRQn, 1);
}

void EXTI15_10_IRQHandler(void)
{
  if (EXTI->PR & EXTI_PR_PR12) {
    EXTI->PR |= EXTI_PR_PR12;
    button_event = EVENT_PRESSED;
  }
}

void CleanupResources(struct netconn *nc, struct netconn *newconn, struct netbuf *buf)
{
  if (newconn != NULL) {
    netconn_close(newconn);
    netconn_delete(newconn);
    newconn = NULL;
  }

  if (nc != NULL) {
    netconn_close(nc);
    netconn_delete(nc);
    nc = NULL;
  }

  if (buf != NULL) {
    netbuf_delete(buf);
    buf = NULL;
  }
}

//---------------------------------------------------------------------------------ANOTHER-CODE-END---
void load_flags_from_flash(void)
{
  boot_os_ok = *(volatile uint8_t *)BOOT_OS_OK_ADDRESS;
  if (boot_os_ok == 0xFF) {
    boot_os_ok = 0;
  }

  sector_enabled = *(volatile uint8_t *)SECTOR_ENABLED_ADDRESS;
  if ((sector_enabled != 1) && (sector_enabled != 2)) {
    sector_enabled = 1;
  }

  log_sector_active = *(volatile uint8_t *)LOG_SECTOR_ACTIVE;
  if(log_sector_active == 0xFF)
  {
    log_sector_active = 1;
  }

  switch (log_sector_active) {
    case 1:
    LOG_START_ADDR = 0x08120000;
    LOG_END_ADDR = 0x0813FFFF;
    break;
    case 2:
    LOG_START_ADDR = 0x08140000;
    LOG_END_ADDR = 0x0815FFFF;
    break;
    case 3:
    LOG_START_ADDR = 0x08160000;
    LOG_END_ADDR = 0x0817FFFF;
    break;
    case 4:
    LOG_START_ADDR = 0x08180000;
    LOG_END_ADDR = 0x0819FFFF;
    break;
    case 5:
    LOG_START_ADDR = 0x081A0000;
    LOG_END_ADDR = 0x081BFFFF;
    break;
    case 6:
    LOG_START_ADDR = 0x081C0000;
    LOG_END_ADDR = 0x081DFFFF;
    break;
    case 7:
    LOG_START_ADDR = 0x081E0000;
    LOG_END_ADDR = 0x081FFFFF;
    break;
  }

  log_ptr = find_next_free_log_address();
  if (log_ptr == 0xFF) {
    Swipe_Log_Sector();
  }
}

static uint8_t first = 1;

HAL_StatusTypeDef Flash_WritePacket(uint8_t *packet, uint16_t packet_size)
{
  taskENTER_CRITICAL();
  HAL_FLASH_Unlock();
  HAL_StatusTypeDef status = HAL_OK;

  if (first) {
    /*
    uint32_t sector_error = 0;
    FLASH_EraseInitTypeDef FLASH_EraseInitStruct;
    FLASH_EraseInitStruct.TypeErase = FLASH_TYPEERASE_SECTORS;
    FLASH_EraseInitStruct.Sector = FLASH_SECTOR_8;
    FLASH_EraseInitStruct.NbSectors = 3;
    FLASH_EraseInitStruct.VoltageRange = FLASH_VOLTAGE_RANGE_3;
    // Clear pending flags (if any)
    __HAL_FLASH_CLEAR_FLAG(FLASH_FLAG_EOP|FLASH_FLAG_OPERR|FLASH_FLAG_WRPERR|
                           FLASH_FLAG_PGAERR|FLASH_FLAG_PGPERR|FLASH_FLAG_PGSERR);

    if (HAL_FLASHEx_Erase(&FLASH_EraseInitStruct, &sector_error) != HAL_OK) {
      return HAL_ERROR;
    }
    */
    address = SECTOR_8_ADDRESS;
    len = 393216;
    next_free_addr = SECTOR_8_ADDRESS;
    first = 0;
  }

  // Проверка на переполнение области
  if ((next_free_addr + packet_size) >= (address + len + 1)) {
    HAL_FLASH_Lock();
    taskEXIT_CRITICAL();
    return HAL_ERROR; // Флеш память переполнена
  }

  // Запись пакета во флеш по байтам (или словам, в зависимости от требований)
  for (uint16_t i = 0; i < packet_size; i += 4) {
    uint32_t data_word = 0xFFFFFFFF;

    // Копируем данные пакета в 32-битное слово
    memcpy(&data_word, &packet[i], (packet_size - i >= 4) ? 4 : (packet_size - i));

    // Записываем слово во флеш
    status = HAL_FLASH_Program(FLASH_TYPEPROGRAM_WORD, next_free_addr + i, data_word);
    if (status != HAL_OK) {
      HAL_FLASH_Lock();
      taskEXIT_CRITICAL();
      return status; // Ошибка при записи
    }
  }

  // Сохраняем указатель на свободную ячейку для следующего пакета
  next_free_addr += packet_size;  // ---invalid
  // Блокировка флеш памяти после записи
  HAL_FLASH_Lock();

  taskEXIT_CRITICAL();
  return status;
}

//---------------------------------------------------------------------------------OS-UDATE-FUNCTIONS---

//возвращает указатель на элемент массива[указанный тег + 0x0d 0x0a 0x0d 0x0a]
uint8_t * parser(uint8_t *buf, uint16_t len, const char *str) {
  uint8_t flags[] = {0x0D, 0x0A, 0x0D, 0x0A};
  size_t str_len = strlen(str);
  size_t buf_len = len;

  for (size_t i = 0; i < buf_len; i++) {
    if (strncmp((char *)&buf[i], str, str_len) == 0) {
      // Проверяем флаги после строки
      if (memcmp(&buf[i + str_len], flags, sizeof(flags)) == 0) {
        // Возвращаем указатель на элемент после флагов
        return &buf[i + str_len + sizeof(flags)];
      }
    }
  }
  return NULL;
}

//вытаскивает числовые значения, переданные в multipart/form-data пакете по тегу
uint16_t parser_num(uint8_t *buf, uint16_t len, const char *str) {
  uint8_t flags[] = {0x22, 0x0D, 0x0A, 0x0D, 0x0A};
  size_t str_len = strlen(str);
  size_t buf_len = len;

  for (size_t i = 0; i < buf_len; i++) {
    if (strncmp((char *)&buf[i], str, str_len) == 0) {
      // Проверяем флаги после строки
      if (i + str_len + sizeof(flags) >= buf_len) {
        // Данные выходят за пределы буфера
        return 0;
      }

      if (memcmp(&buf[i + str_len], flags, sizeof(flags)) == 0) {
        // Позиция начала числа
        size_t num_start = i + str_len + sizeof(flags);

        // Ищем конец числа (0x0D 0x0A)
        size_t num_end = num_start;
        while (num_end + 1 < buf_len && !(buf[num_end] == 0x0D && buf[num_end + 1] == 0x0A)) {
          num_end++;
        }

        if (num_end + 1 >= buf_len) {
          // Конец строки не найден
          return 0;
        }

        // Извлекаем строку числа
        size_t num_len = num_end - num_start;
        if (num_len == 0 || num_len > 5) { // Число не может быть больше 65535
          return 0;
        }

        char num_str[6] = {0}; // Максимум 5 символов + \0
        memcpy(num_str, &buf[num_start], num_len);
        num_str[num_len] = '\0';

        // Преобразуем строку в число
        uint16_t result = (uint16_t)atoi(num_str);
        return result;
      }
    }
  }
  return 0; // Если строка не найдена
}

uint8_t buf_for_bad_chank[1300] = {0};

#define RX_BUF_SIZE 2000

err_t httpd_post_receive_data(void *connection, struct pbuf *p)
{
      /* ---------- статический конструктор одного чанка ---------- */
    static struct {
        uint8_t buf[RX_BUF_SIZE];
        uint16_t len;            /* уже получено */
        uint16_t expected_len; /* 0, пока не знаем, сколько должно быть */
    } rx = { .len = 0, .expected_len = 0 };

    uint16_t packet_size = p->tot_len;
    uint8_t *payload     = (uint8_t *)p->payload;

    /* ---------- 1. копируем фрагмент ---------- */
    if ((uint32_t)rx.len + packet_size > sizeof(rx.buf)) {
        rx.len = rx.expected_len = 0;         /* сброс при переполнении */
        httpd_post_data_recved(connection, packet_size);
        pbuf_free(p);
        return ERR_BUF;
    }
    memcpy(rx.buf + rx.len, payload, packet_size);
    rx.len += packet_size;

    /* ---------- 2. пробуем уточнить, сколько нужно всего ---------- */
    {
        uint16_t raw_len    = parser_num(rx.buf, rx.len, "rawDataLength");
        uint8_t *stream_ptr = (uint8_t *)parser(rx.buf, rx.len, "stream");

        if (raw_len && stream_ptr) {
            uint16_t header_len = (uint16_t)(stream_ptr - rx.buf);
            uint16_t candidate_len = header_len + raw_len;

            if (candidate_len > rx.expected_len && candidate_len <= RX_BUF_SIZE)
                rx.expected_len = candidate_len; /* берём самое большое */
        }
    }

    /* ---------- 3. чанк ещё не собран — ждём ---------- */
    if (rx.expected_len == 0 || rx.len < rx.expected_len) {
        httpd_post_data_recved(connection, packet_size);
        pbuf_free(p);
        return ERR_OK;
    }

    /* ---------- 4. чанк полный, работаем ---------- */
    uint8_t *chunk     = rx.buf;
    uint16_t chunk_size = rx.len;

    uint16_t packetNow = parser_num(chunk, chunk_size, "chunkIndex");
    uint16_t packetTotal = parser_num(chunk, chunk_size, "totalChunks");
    uint16_t BinDataLength = parser_num(chunk, chunk_size, "rawDataLength");
    uint8_t *packetData = (uint8_t *)parser(chunk, chunk_size, "stream");

    if (packetNow == packetTotal - 1) {     /* последний чанк — тащим CRC */
        crc_os =
            ((uint32_t)packetData[BinDataLength-4] << 24) |
            ((uint32_t)packetData[BinDataLength-3] << 16) |
            ((uint32_t)packetData[BinDataLength-2] << 8) |
             (uint32_t)packetData[BinDataLength-1];
        memset(&packetData[BinDataLength-4], 0xFF, 4);
    }

    if (Flash_WritePacket(packetData, BinDataLength) != HAL_OK) {
        boot_flag_new = 1;
        WriteFlash((FlashDataType)0, 0);
        rx.len = rx.expected_len = 0;
        return ERR_BUF;
    }

    if (packetNow == packetTotal - 1) {
        log_ready = 1;
        boot_flag_new = 1;
        WriteFlash((FlashDataType)0, 0);
    }

    httpd_post_data_recved(connection, packet_size);
    pbuf_free(p);

    /* ---------- 5. обнуляем буфер, ждём следующий ----------- */
    rx.len = 0;
    rx.expected_len = 0;
    return ERR_OK;
  /*
  log_ready = 0;
  static uint16_t packet_cnt = 0;
  static uint16_t packet_cnt_dab = 0; // флаг: собираем ли недочанк
  static uint16_t bad_chunk_pos = 0;  // куда дописывать в buf_for_bad_chank

  // Извлечение данных из pbuf
  uint16_t packet_size = p->tot_len; // Общий размер данных пакета
  uint8_t *payload = (uint8_t *)p->payload; // указатель на полезные данные

  uint16_t packetNow = parser_num((uint8_t*)payload, packet_size, "chunkIndex");
  uint16_t packetTotal = parser_num((uint8_t*)payload, packet_size, "totalChunks");

  // Если пришёл маленький фрагмент — собираем его
  if ((packet_size < 1200) && (packetNow != (packetTotal-1)))
  {
    if (!packet_cnt_dab)
    {
      // часть чанка: копируем в буфер и запоминаем позицию
      if (packet_size > sizeof(buf_for_bad_chank)) {
        // Слишком большой кусок для буфера — ошибка
        pbuf_free(p);
        return ERR_BUF;
      }
      memcpy(buf_for_bad_chank, payload, packet_size);
      bad_chunk_pos = packet_size;
      packet_cnt_dab = 1;

      // Сообщаем стеку, что данные приняты и ждём следующий вызов
      httpd_post_data_recved(connection, packet_size);
      pbuf_free(p);
      return ERR_OK;
    } else {
      // Второй фрагмент: доклеиваем чанк и дальше продолжаем обработку
      if ((uint32_t)bad_chunk_pos + packet_size > sizeof(buf_for_bad_chank)) {
        // Переполнение буфера — сбрасываем состояние и возвращаем ошибку
        bad_chunk_pos = 0;
        packet_cnt_dab = 0;
        pbuf_free(p);
        return ERR_BUF;
      }

      memcpy(buf_for_bad_chank + bad_chunk_pos, payload, packet_size);
      // Теперь общий указатель на данные — наш буфер
      payload = buf_for_bad_chank;
      packet_size = bad_chunk_pos + packet_size;

      // Сброс состояния сборки
      bad_chunk_pos = 0;
      packet_cnt_dab = 0;
      // Не освобождаем p тут — освободим в конце как обычно
    }
  }

  // дальше — обычная обработка целого чанка
  packetNow = parser_num((uint8_t*)payload, packet_size, "chunkIndex");
  packetTotal = parser_num((uint8_t*)payload, packet_size, "totalChunks");
  uint16_t BinDataLength = parser_num((uint8_t*)payload, packet_size, "rawDataLength");

  // Получаем указатель на бинарные данные в пакете
  uint8_t *packetData = parser((uint8_t*)payload, packet_size, "stream");

  packet_cnt++;

  if (packetNow == (packetTotal-1))
  {
    crc_os =
      ((uint32_t)packetData[BinDataLength-4] << 24) |
        ((uint32_t)packetData[BinDataLength-3] << 16) |
          ((uint32_t)packetData[BinDataLength-2] << 8)  |
            ((uint32_t)packetData[BinDataLength-1]);
    packetData[BinDataLength-4] = 0xFF;
    packetData[BinDataLength-1] = 0xFF;
    packetData[BinDataLength-2] = 0xFF;
    packetData[BinDataLength-3] = 0xFF;
  }

  if (Flash_WritePacket(packetData, BinDataLength) != HAL_OK)
  {
    pbuf_free(p);
    boot_flag_new = 1;
    WriteFlash((FlashDataType)0, 0);
    return ERR_BUF;
  }

  httpd_post_data_recved(connection, packet_size);
  pbuf_free(p);

  if(packetNow == (packetTotal-1))
  {
    boot_flag_new = 1;
    WriteFlash((FlashDataType)0, 0);
  }

  return ERR_OK;
*/
}

err_t httpd_post_begin(void *connection, const char *uri, const char *http_request,
                       u16_t http_request_len, int content_len, char *response_uri,
                       u16_t response_uri_len, u8_t *post_auto_wnd)
{
    //xSemaphoreTake(xPacketSaved, portMAX_DELAY);
    *post_auto_wnd = 0;
    return ERR_OK;
}

void httpd_post_finished(void *connection, char *response_uri, u16_t response_uri_len)
{
  const char *success_message = "/update.shtml"; // Путь к странице успешного ответа
  size_t message_len = strlen(success_message);

  strncpy(response_uri, success_message, response_uri_len - 1);
  response_uri[response_uri_len - 1] = '\0';
}

void CRC_Config(void)
{
  // Указываем базовый адрес
  hcrc.Instance = CRC;

  // Вызываем инициализацию HAL
  if (HAL_CRC_Init(&hcrc) != HAL_OK) {
    // Если что-то пошло не так, можно добавить обработку ошибки
    while (1);
  }
}

uint32_t calculate_flash_crc(uint32_t start_address, uint32_t end_address)
{
    __HAL_CRC_DR_RESET(&hcrc);

    // Проверяем, что адреса выровнены по 4 байта
    if (start_address % 4 != 0) {
        return 0xFFFFFFFF; // Ошибка
    }

    // Вычисляем длину данных в 32-битных словах
    uint32_t length = (end_address - start_address) / 4;

    // Преобразуем адреса в указатели на uint32_t
    uint32_t* data = (uint32_t*)start_address;

    uint32_t answer = HAL_CRC_Calculate(&hcrc, data, length);
    // Вычисляем
    uint32_t reversed_answer = 0;
    reversed_answer |= (answer & 0x000000FF) << 24;  // младший байт в старший
    reversed_answer |= (answer & 0x0000FF00) << 8;   // второй байт на второй
    reversed_answer |= (answer & 0x00FF0000) >> 8;   // третий байт на третий
    reversed_answer |= (answer & 0xFF000000) >> 24;  // старший байт на младший

    return reversed_answer;
}

static void vTestBlockReleaseCb(TimerHandle_t xTimer)
{
  button_block = nBLOCK_BUTTON;
}

//---------------------------------------------------------------------------------

//--------------------------RMS--BY--MACROS----------------------------------------

//--------------------------------------------------------------------------------------Positive Leakage Trend Analysis

//------------------------------------
void initBuffer10Min(CircularBuffer10Min *buffer) {
  for (uint8_t i = 0; i < MINUTE_10_SIZE; i++) {
      buffer->arr[i] = 0;
  }
  buffer->index = 0;
  buffer->sum = 0;
}

void initBuffer1Hour(CircularBuffer1Hour *buffer) {
  for (uint8_t i = 0; i < HOUR_1_SIZE; i++) {
    buffer->arr[i] = 0;
  }
  buffer->index = 0;
  buffer->sum = 0;
}

void initBuffer2Day(CircularBuffer2Day *buffer) {
  for (uint8_t i = 0; i < DAY_2_SIZE; i++) {
    buffer->arr[i] = 0;
  }
  buffer->index = 0;
  buffer->sum = 0;
}
//-----------------------------------------

//---------------------------------------------

void addValue10Min(CircularBuffer10Min *buffer, uint16_t value) {
  // Вычитаем старое значение из суммы
  buffer->sum -= buffer->arr[buffer->index];
  // Добавляем новое значение
  buffer->arr[buffer->index] = value;
  buffer->sum += value;
  // Сдвигаем индекс
  buffer->index = (buffer->index + 1) % MINUTE_10_SIZE;
}

void addValue1Hour(CircularBuffer1Hour *buffer, uint16_t value) {
  buffer->sum -= buffer->arr[buffer->index];
  buffer->arr[buffer->index] = value;
  buffer->sum += value;
  buffer->index = (buffer->index + 1) % HOUR_1_SIZE;
}

void addValue2Day(CircularBuffer2Day *buffer, uint16_t value) {
  buffer->sum -= buffer->arr[buffer->index];
  buffer->arr[buffer->index] = value;
  buffer->sum += value;
  buffer->index = (buffer->index + 1) % DAY_2_SIZE;
}

static uint8_t RTC_IsTimeValid(void)
{
    return ((RTC->ISR & RTC_ISR_INITS) != 0);   // 1 → дата/время уже заданы
}

void RTC_Init(void)
{
  __HAL_RCC_PWR_CLK_ENABLE();
  HAL_PWR_EnableBkUpAccess();

  //__HAL_RCC_BACKUPRESET_FORCE();
  //__HAL_RCC_BACKUPRESET_RELEASE();

  __HAL_RCC_LSI_ENABLE();
  while (__HAL_RCC_GET_FLAG(RCC_FLAG_LSIRDY) == RESET) {}

  __HAL_RCC_RTC_CONFIG(RCC_RTCCLKSOURCE_LSI);

  __HAL_RCC_RTC_ENABLE();

  //HAL_Delay(100);

  RTC_TimeTypeDef sTime = {0};
  RTC_DateTypeDef sDate = {0};

  /** Инициализация RTC с использованием LSI**/
  hrtc.Instance = RTC;
  hrtc.Init.HourFormat = RTC_HOURFORMAT_24;
  hrtc.Init.AsynchPrediv = 127;
  hrtc.Init.SynchPrediv = 255;
  hrtc.Init.OutPut = RTC_OUTPUT_DISABLE;
  hrtc.Init.OutPutPolarity = RTC_OUTPUT_POLARITY_HIGH;
  hrtc.Init.OutPutType = RTC_OUTPUT_TYPE_OPENDRAIN;

  HAL_StatusTypeDef rtc_status;
  rtc_status = HAL_RTC_Init(&hrtc);

  if (rtc_status != HAL_OK) {
    // Обработка ошибки инициализации
    Error_Handler();
  }

  if (!RTC_IsTimeValid())          // <--- проверка
  {
    REGISTERS[4] |= 0x04;
    /** Установка времени: 00:00:00 **/
    sTime.Hours = 0;
    sTime.Minutes = 0;
    sTime.Seconds = 0;
    sTime.TimeFormat = RTC_HOURFORMAT12_AM;
    sTime.DayLightSaving = RTC_DAYLIGHTSAVING_NONE;
    sTime.StoreOperation = RTC_STOREOPERATION_RESET;
    if (HAL_RTC_SetTime(&hrtc, &sTime, RTC_FORMAT_BIN) != HAL_OK) {
      Error_Handler();
    }

    /** Установка даты: 01.01.2025 **/
    sDate.WeekDay = RTC_WEEKDAY_WEDNESDAY;
    sDate.Month = RTC_MONTH_JANUARY;
    sDate.Date = 1;
    sDate.Year = 25; // 2025 год (HAL использует 2 последних цифры)
    if (HAL_RTC_SetDate(&hrtc, &sDate, RTC_FORMAT_BIN) != HAL_OK) {
      Error_Handler();
    }
  }
}

uint16_t getAverage10Min(CircularBuffer10Min *buffer) {
    return (uint16_t)buffer->sum / MINUTE_10_SIZE;
}

uint16_t getAverage1Hour(CircularBuffer1Hour *buffer) {
    return (uint16_t)buffer->sum / HOUR_1_SIZE;
}

uint16_t getAverage2Day(CircularBuffer2Day *buffer) {
    return (uint16_t)buffer->sum / DAY_2_SIZE;
}
//----------------------------------------------RTC-SECTION--------------------

void save_time_to_rtc(uint8_t *arr)
{
  uint16_t mask = (1 << 2);
  REGISTERS[4] &= ~mask;

  uint8_t day   = (arr[0] - '0') * 10 + (arr[1] - '0');
  uint8_t month = (arr[3] - '0') * 10 + (arr[4] - '0');
  uint16_t year = (arr[6] - '0') * 1000 + (arr[7] - '0') * 100 +
    (arr[8] - '0') * 10   + (arr[9] - '0');
  uint8_t hour  = (arr[11] - '0') * 10 + (arr[12] - '0');
  uint8_t minute = (arr[14] - '0') * 10 + (arr[15] - '0');
  uint8_t second = (arr[17] - '0') * 10 + (arr[18] - '0');

  // Настройка времени RTC
  RTC_TimeTypeDef sTime = {0};
  sTime.Hours = hour;
  sTime.Minutes = minute;
  sTime.Seconds = second;
  sTime.TimeFormat = RTC_HOURFORMAT12_AM;
  sTime.DayLightSaving = RTC_DAYLIGHTSAVING_NONE;
  sTime.StoreOperation = RTC_STOREOPERATION_RESET;

  if (HAL_RTC_SetTime(&hrtc, &sTime, RTC_FORMAT_BIN) != HAL_OK)
  {
    Error_Handler();
  }

  // Настройка даты RTC
  RTC_DateTypeDef sDate = {0};
  sDate.Date = day;
  sDate.Month = month;
  sDate.Year = year % 100;  // HAL использует две последние цифры года
  sDate.WeekDay = RTC_WEEKDAY_SUNDAY;

  if (HAL_RTC_SetDate(&hrtc, &sDate, RTC_FORMAT_BIN) != HAL_OK)
  {
    Error_Handler();
  }
}

void get_current_timestamp(uint8_t *timestamp)
{
    RTC_TimeTypeDef sTime;
    RTC_DateTypeDef sDate;

    HAL_RTC_GetTime(&hrtc, &sTime, RTC_FORMAT_BIN);
    HAL_RTC_GetDate(&hrtc, &sDate, RTC_FORMAT_BIN);

    timestamp[0] = sTime.Seconds;
    timestamp[1] = sTime.Minutes;
    timestamp[2] = sTime.Hours;
    timestamp[3] = sDate.Date;
    timestamp[4] = sDate.Month;
    timestamp[5] = sDate.Year;
}

//------------------------------------------------LOG-SECTION-------------------
void write_to_log(log_code code, uint8_t log_data[], uint16_t copy_len)
{

  /* вынесена в шапку

  typedef struct {
  uint8_t timestamp[6];  // ss:mm:hh:dd:mm:yy (временная метка)
  uint8_t event_code;    // код события
  uint8_t data[5];       //поле данных
} LogEntry;
  //12 байт
  */

  //код события (основные)
  //0x30 - изменение тока утечки на 10%
  //0x31 - ТЕСТ
  //0x32 - Предупреждение
  //0x33 - сработала защита

  //код события (настройки)
  //0х02 - IP адрес
  //0х03 - Маска подсети
  //0х04 - Шлюз
  //0х05 - REGISTERS[2] (состоянее реле изменилось (кнопка в вебе, moodbus, аппаратная защита и т.д.) (0х00/0х01)
  //0x07 - Приняли новое П.О.
  //0x09 - USART скорость (4 байта, которые надо собрать в 4 первые цифры)
  //0x10 - USART четность (char)(прям словом ~odd)
  //0x11 - USART стоп бит

  //0х12 - C_phase_A (все значения тут - float, без скоращения)
  //0x13 - C_phase_B
  //0x14 - C_phase_C
  //0x15 - R_leak_A
  //0x16 - R_leak_B
  //0x17 - R_leak_C

  //0x18 - TARGET_VALUE (uint8_t пороговое значение тока)
  //0x19 - WARNING_VALUE (uint8_t пороговое значение тока)
  //0x20 - Аппаратная защита (0/1)

  if (log_ready) {
    uint32_t startAddress = log_ptr;
    uint8_t final_data[12] = {0};

    LogEntry frame = {0};

    while ((log_ptr + sizeof(LogEntry)) >= LOG_END_ADDR)
    {
      Swipe_Log_Sector();
      startAddress = log_ptr;
    }

    if (startAddress < 0x08120000) {
      return;
    }

    get_current_timestamp(frame.timestamp);

    frame.event_code = code;

    memset(frame.data, 0, sizeof(frame.data)); // Заполняем массив данных нулями
    memcpy(frame.data, log_data, copy_len);

    memcpy(final_data, &frame, sizeof(frame));
    HAL_FLASH_Unlock();

    for (uint32_t i = 0; i < sizeof(LogEntry); i++) {
      if (HAL_FLASH_Program(FLASH_TYPEPROGRAM_BYTE, startAddress + i, final_data[i]) != HAL_OK) {
        HAL_FLASH_Lock();
        return;
      }
    }

    HAL_FLASH_Lock();

    log_ptr += sizeof(LogEntry);
  }
}

static uint8_t flash_read_byte(uint32_t address)
{
    return *((volatile uint8_t*)address);
}

static void flash_write_byte(uint32_t address, uint8_t value)
{
  taskENTER_CRITICAL();
  HAL_FLASH_Unlock();

  if (HAL_FLASH_Program(FLASH_TYPEPROGRAM_BYTE, address, value) != HAL_OK) {
    HAL_FLASH_Lock();
    taskEXIT_CRITICAL();
    return;
  }

  HAL_FLASH_Lock();
  taskEXIT_CRITICAL();
}

uint32_t find_next_free_log_address(void)
{
  uint32_t addr = LOG_END_ADDR - 1;

  // 1. Ищем «последний занятый байт», т.е. первый не 0xFF с конца.
  //    Если таких нет, значит память пуста.
  while (1) {
    // Если ушли за начало лога, значит вся область пуста.
    if (addr < LOG_START_ADDR) {
      log_ready = 1;
      // Нет записанных данных
      return LOG_START_ADDR;
    }

    if (flash_read_byte(addr) != 0xFF) {
      // Нашли байт, который НЕ равен 0xFF – это и будет последний занятый байт.
      break;
    }
    addr--;
  }

  // 2. Подсчитываем, сколько байт всего занято
  //    (LOG_START_ADDR ... addr включительно).
  //    Например, если addr = LOG_START_ADDR, то размер = 1.
  uint32_t used_size = (addr - LOG_START_ADDR) + 1;

  log_ready = 1;

  // 3. Проверяем кратность размеру записи (12 байт).
  uint32_t remainder = used_size % LOG_ENTRY_SIZE;
  if (remainder == 0) {
    // 3.1. Если всё чётко по границам 12 байт,
    //      то свободный адрес – сразу за последним занятым байтом.
    if ((LOG_START_ADDR + used_size) < LOG_END_ADDR) {
      return LOG_START_ADDR + used_size;
    } else {
      return 0xFF; //заполнено все
    }
  } else {
    // 3.2. Иначе — нужно «дозаписать» остаток до ближайших 12 байт символами 0xF0,
    //      чтобы при следующем чтении было понятно, что эта запись недействительна.

    // Адрес начала «обрывка».
    // Текущее «начало» последней записи по границе 12 байт:
    // Например, если used_size=25, remainder=1, тогда последняя корректная граница – 24.
    uint32_t partial_start = (LOG_START_ADDR + used_size) - remainder;
    // Верхняя граница, которую мы зальём 0xF0, чтобы закрыть 12-байтную запись:
    uint32_t partial_end   = partial_start + LOG_ENTRY_SIZE - 1;
    if (partial_end >= LOG_END_ADDR) {
      // На всякий случай проверяем, чтобы не выйти за пределы.
      return 0xFF;
    }

    // Заполняем нужный диапазон 0xF0, превращая остаток в "невалидную запись".
    for (uint32_t fill_addr = partial_start; fill_addr <= partial_end; fill_addr++) {
      flash_write_byte(fill_addr, 0xF0);
    }

    // Теперь свободный адрес — сразу за этой 12-байтной «фейковой» записью.
    return (partial_end + 1);
  }
}

__attribute__((section(".ramfunc")))
void Swipe_Log_Sector()
{
  if (!flash_block) {
    uint32_t sector_error = 0;
    FLASH_EraseInitTypeDef FLASH_EraseInitStruct;
    FLASH_EraseInitStruct.TypeErase = FLASH_TYPEERASE_SECTORS;
    FLASH_EraseInitStruct.NbSectors = 1;
    FLASH_EraseInitStruct.VoltageRange = FLASH_VOLTAGE_RANGE_3;

    __HAL_FLASH_CLEAR_FLAG(FLASH_FLAG_EOP|FLASH_FLAG_OPERR|FLASH_FLAG_WRPERR|
                           FLASH_FLAG_PGAERR|FLASH_FLAG_PGPERR|FLASH_FLAG_PGSERR);

    log_ready = 0;
    log_sector_active = (log_sector_active % 7) + 1;
    __disable_irq();

    __HAL_FLASH_DATA_CACHE_DISABLE();
    __HAL_FLASH_DATA_CACHE_RESET();

    taskENTER_CRITICAL();
    HAL_FLASH_Unlock();

    switch (log_sector_active) {
      case 1: {
        LOG_START_ADDR = 0x08120000;
        log_ptr = 0x08120000;
        LOG_END_ADDR = 0x0813FFFF;
        FLASH_EraseInitStruct.Sector = FLASH_SECTOR_17;
        HAL_FLASHEx_Erase(&FLASH_EraseInitStruct, &sector_error);
        //FLASH_Erase_Sector(FLASH_SECTOR_17, FLASH_VOLTAGE_RANGE_3);
        break;
      }

      case 2: {
        LOG_START_ADDR = 0x08140000;
        log_ptr = LOG_START_ADDR;
        LOG_END_ADDR = 0x0815FFFF;
        FLASH_EraseInitStruct.Sector = FLASH_SECTOR_18;
        HAL_FLASHEx_Erase(&FLASH_EraseInitStruct, &sector_error);
        //FLASH_Erase_Sector(FLASH_SECTOR_18, FLASH_VOLTAGE_RANGE_3);
        break;
      }
      case 3: {
        LOG_START_ADDR = 0x08160000;
        log_ptr = LOG_START_ADDR;
        LOG_END_ADDR = 0x0817FFFF;
        FLASH_EraseInitStruct.Sector = FLASH_SECTOR_19;
        HAL_FLASHEx_Erase(&FLASH_EraseInitStruct, &sector_error);
        //FLASH_Erase_Sector(FLASH_SECTOR_19, FLASH_VOLTAGE_RANGE_3);
        break;
      }
      case 4: {
        LOG_START_ADDR = 0x08180000;
        log_ptr = LOG_START_ADDR;
        LOG_END_ADDR = 0x0819FFFF;
        FLASH_EraseInitStruct.Sector = FLASH_SECTOR_20;
        HAL_FLASHEx_Erase(&FLASH_EraseInitStruct, &sector_error);
        //FLASH_Erase_Sector(FLASH_SECTOR_20, FLASH_VOLTAGE_RANGE_3);
        break;
      }
      case 5:{
        LOG_START_ADDR = 0x081A0000;
        log_ptr = LOG_START_ADDR;
        LOG_END_ADDR = 0x081BFFFF;
        FLASH_EraseInitStruct.Sector = FLASH_SECTOR_21;
        HAL_FLASHEx_Erase(&FLASH_EraseInitStruct, &sector_error);
        //FLASH_Erase_Sector(FLASH_SECTOR_21, FLASH_VOLTAGE_RANGE_3);
        break;
      }
      case 6:{
        LOG_START_ADDR = 0x081C0000;
        log_ptr = LOG_START_ADDR;
        LOG_END_ADDR = 0x081DFFFF;
        FLASH_EraseInitStruct.Sector = FLASH_SECTOR_22;
        HAL_FLASHEx_Erase(&FLASH_EraseInitStruct, &sector_error);
        //FLASH_Erase_Sector(FLASH_SECTOR_22, FLASH_VOLTAGE_RANGE_3);
        break;
      }
      case 7:{
        LOG_START_ADDR = 0x081E0000;
        log_ptr = LOG_START_ADDR;
        LOG_END_ADDR = 0x081FFFF8;
        FLASH_EraseInitStruct.Sector = FLASH_SECTOR_23;
        HAL_FLASHEx_Erase(&FLASH_EraseInitStruct, &sector_error);
        //FLASH_Erase_Sector(FLASH_SECTOR_23, FLASH_VOLTAGE_RANGE_3);
        break;
      }
    }
    HAL_FLASH_Lock();
    taskEXIT_CRITICAL();

    __HAL_FLASH_DATA_CACHE_ENABLE();
    __enable_irq();

    neead_write_flash = 1;

    //WriteFlash(0,0);
    log_ready = 1;
  }
}

uint8_t save_time_unix(uint64_t timestamp)
{
  uint32_t sec    = timestamp % 60;
  uint32_t minute = (timestamp / 60) % 60;
  uint32_t hour   = (timestamp / 3600) % 24;
  uint32_t days   = timestamp / 86400UL;

  int year = 1970;
  while (1) {
    int daysInYear = ((year % 4 == 0 && (year % 100 != 0 || year % 400 == 0)) ? 366 : 365);
    if (days >= (uint32_t)daysInYear) {
      days -= daysInYear;
      year++;
    } else break;
  }

  int month = 1;
  int daysInMonth[12] = {31,28,31,30,31,30,31,31,30,31,30,31};
  if (year % 4 == 0 && (year % 100 != 0 || year % 400 == 0)) daysInMonth[1] = 29;

  while (days >= (uint32_t)daysInMonth[month - 1]) {
    days -= daysInMonth[month - 1];
    month++;
    if (month > 12) { month = 12; break; } // safety
  }
  int day = days + 1;

  // подготовка структуры HAL
  RTC_TimeTypeDef sTime = {0};
  sTime.Hours = hour;
  sTime.Minutes = minute;
  sTime.Seconds = sec;
  sTime.TimeFormat = RTC_HOURFORMAT_24;
  sTime.DayLightSaving = RTC_DAYLIGHTSAVING_NONE;
  sTime.StoreOperation = RTC_STOREOPERATION_RESET;

  if (HAL_RTC_SetTime(&hrtc, &sTime, RTC_FORMAT_BIN) != HAL_OK) {
    return 1;
  }

  RTC_DateTypeDef sDate = {0};
  sDate.Date = day;
  sDate.Month = month;
  sDate.Year = year % 100;
  if (HAL_RTC_SetDate(&hrtc, &sDate, RTC_FORMAT_BIN) != HAL_OK) {
    return 1;
  }

  return 0; // success
}

void apply_time_from_registers(void)
{
  uint16_t r5, r6, r7, r8;
  // критическая секция — вариант если baremetal:
  __disable_irq();
  r5 = REGISTERS[5];
  r6 = REGISTERS[6];
  r7 = REGISTERS[7];
  r8 = REGISTERS[8];
  __enable_irq();

  // собираем 64-бит (предполагаем: REGISTERS[5] = MSW)
  uint64_t timestamp = ((uint64_t)r5 << 48) | ((uint64_t)r6 << 32) | ((uint64_t)r7 << 16) | (uint64_t)r8;

  if (timestamp == 0) {
    // некорректно — отбиваемся, очищаем APPLY и не ставим SET
    // атомарно очистим флаг APPLY
    __disable_irq();
    REGISTERS[4] &= ~TIME_FLAG_APPLY;
    __enable_irq();
    return;
  }

  uint8_t res = save_time_unix(timestamp);
  __disable_irq();
  // очистим APPLY
  REGISTERS[4] &= ~TIME_FLAG_APPLY;
  if (res == 0)
  {
    REGISTERS[4] &= ~TIME_FLAG_SET;
    REGISTERS[5] = 0;
    REGISTERS[6] = 0;
    REGISTERS[7] = 0;
    REGISTERS[8] = 0;
  }
  else
  {
    REGISTERS[4] |= TIME_FLAG_SET;
    REGISTERS[5] = 0;
    REGISTERS[6] = 0;
    REGISTERS[7] = 0;
    REGISTERS[8] = 0;
  }
  __enable_irq();
}

void timerCreate(void)
{
/* 10-минутный однократный таймер для флага реле */
    xRelayFlagTimer = xTimerCreate("RelFlag",
                                   pdMS_TO_TICKS(600000),   // 10 мин
                                   pdFALSE,                 // одноразовый
                                   NULL,                    // id не нужен
                                   vRelayFlagCallback);      // <<< наш коллбэк
    configASSERT(xRelayFlagTimer);
}

void timerStart(void)
{
    relay_pause = 1;//индикация молния (была сработка не более 10мин назад)

    //xTimerStop(xRelayFlagTimer, 0);          // на случай, если уже тикает
    // #define xTimerStop( xTimer, xTicksToWait ) xTimerGenericCommand( ( xTimer ), tmrCOMMAND_STOP, 0U, NULL, ( xTicksToWait ) )
    //xTimerStart(xRelayFlagTimer, 0);
    // #define xTimerStart( xTimer, xTicksToWait ) xTimerGenericCommand( ( xTimer ), tmrCOMMAND_START, ( xTaskGetTickCount() ), NULL, ( xTicksToWait ) )
    xTimerReset(xRelayFlagTimer, 0);
    // #define xTimerReset( xTimer, xTicksToWait ) xTimerGenericCommand( ( xTimer ), tmrCOMMAND_RESET, ( xTaskGetTickCount() ), NULL, ( xTicksToWait ) )
}

void vRelayFlagCallback(TimerHandle_t xTimer)
{
   relay_pause = 0;
}

void timerStartCreate(void)
{
  /* 20 мс таймер для отложенного старта измерений adc */
    xStartADCtimer = xTimerCreate("StartADC",
                                   pdMS_TO_TICKS(20),   // 20 мс
                                   pdFALSE,                 // одноразовый
                                   NULL,                    // id не нужен
                                   vStartADCtimerCallback);      // <<< наш коллбэк
    configASSERT(xStartADCtimer);
    xTimerStart(xStartADCtimer, 0);
}

void vStartADCtimerCallback(TimerHandle_t xTimer)
{
   HAL_ADC_Start_DMA(&hadc1, (uint32_t*)adcBuffer, ADC_BUF);
}

/* USER CODE END Application */
